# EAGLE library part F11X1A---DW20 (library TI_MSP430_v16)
*** MSP430F11x1A *** DW20

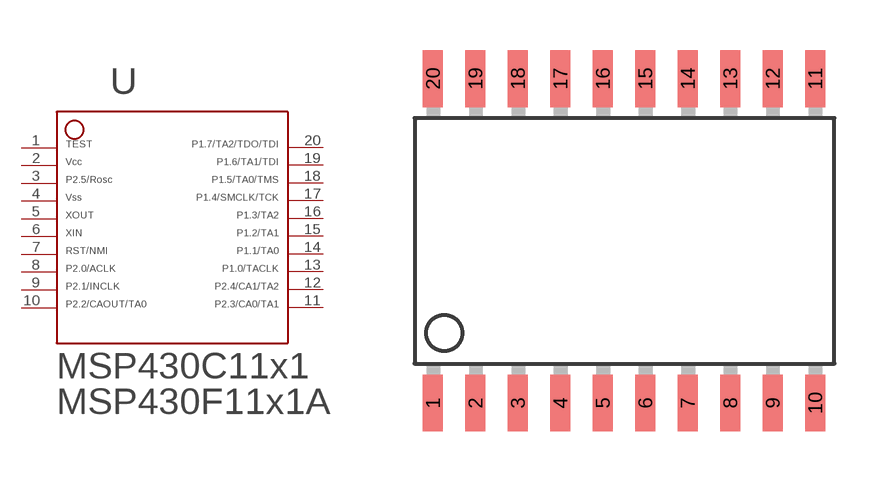
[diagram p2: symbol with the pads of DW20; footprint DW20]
Designator prefix -

## F11X1A---DW20  [DW20]
1  1  in
2  2  pwr
3  3
4  4  pwr
5  5  out
6  6  in
7  7  in
8  8
9  9
10  10
11  11
12  12
13  13
14  14
15  15
16  16
17  17
18  18
19  19
20  20

## Footprint DW20 (pad centres in mm)
*** TI: DW *** JEDEC: R-PDSO-G20 *** 20 PINS ***
smd 0.6 x 1.7: 1 -5.715,-4.85; 2 -4.445,-4.85; 3 -3.175,-4.85; 4 -1.905,-4.85; 5 -0.635,-4.85; 6 0.635,-4.85; 7 1.905,-4.85; 8 3.175,-4.85; 9 4.445,-4.85; 10 5.715,-4.85; 11 5.715,4.85; 12 4.445,4.85; 13 3.175,4.85; 14 1.905,4.85; 15 0.635,4.85; 16 -0.635,4.85; 17 -1.905,4.85; 18 -3.175,4.85; 19 -4.445,4.85; 20 -5.715,4.85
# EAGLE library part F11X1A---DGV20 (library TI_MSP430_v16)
*** MSP430F11x1A *** DGV20

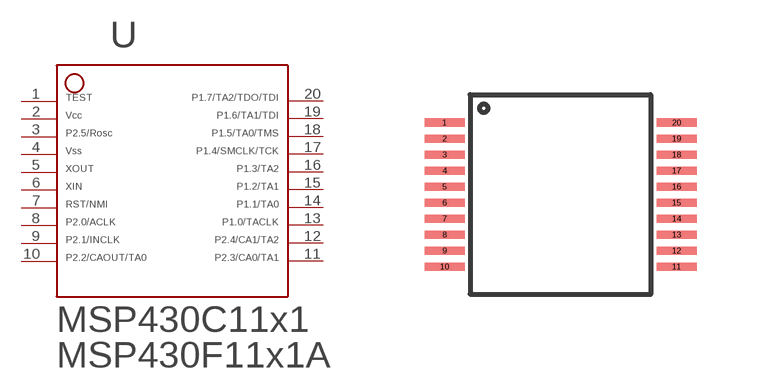
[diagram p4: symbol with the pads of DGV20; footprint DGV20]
Designator prefix -

## F11X1A---DGV20  [DGV20]
1  1  in
2  2  pwr
3  3
4  4  pwr
5  5  out
6  6  in
7  7  in
8  8
9  9
10  10
11  11
12  12
13  13
14  14
15  15
16  16
17  17
18  18
19  19
20  20

## Footprint DGV20 (pad centres in mm)
*** TI: DGV *** JEDEC: R-PDSO-G20 *** 20 PINS ***
smd 1 x 0.2: 1 -2.9,1.8; 2 -2.9,1.4; 3 -2.9,1; 4 -2.9,0.6; 5 -2.9,0.2; 6 -2.9,-0.2; 7 -2.9,-0.6; 8 -2.9,-1; 9 -2.9,-1.4; 10 -2.9,-1.8; 11 2.9,-1.8; 12 2.9,-1.4; 13 2.9,-1; 14 2.9,-0.6; 15 2.9,-0.2; 16 2.9,0.2; 17 2.9,0.6; 18 2.9,1; 19 2.9,1.4; 20 2.9,1.8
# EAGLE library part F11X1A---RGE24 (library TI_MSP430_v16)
*** MSP430F11x1A *** RGE24

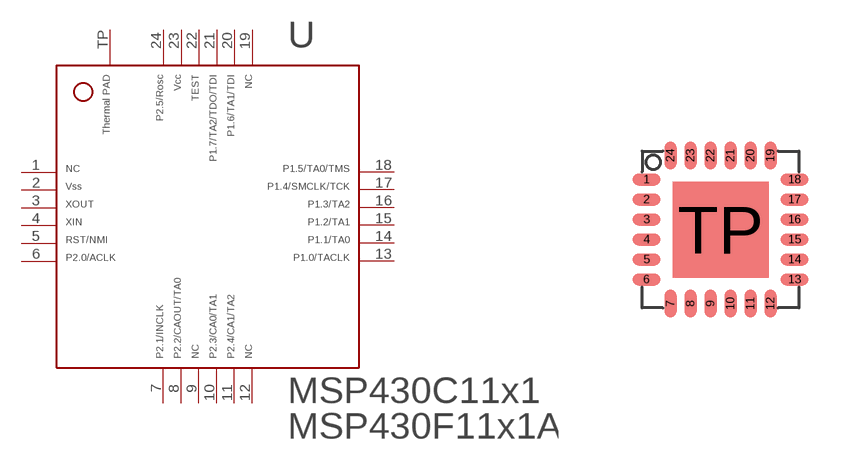
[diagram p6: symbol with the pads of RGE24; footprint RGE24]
Designator prefix -

## F11X1A---RGE24  [RGE24]
1  1  nc
2  2  pwr
3  3  out
4  4  in
5  5  in
6  6
7  7
8  8
9  9  nc
10  10
11  11
12  12  nc
13  13
14  14
15  15
16  16
17  17
18  18
19  19  nc
20  20
21  21
22  22  in
23  23  pwr
24  24
TP  25  pwr

## Footprint RGE24 (pad centres in mm)
*** TI: RGE *** JEDEC: S-PQFP-N24 *** 24 PINS *** ---> PIN25 (exposed thermal die pad) should be connected with GND
smd 0.7 x 0.3: 1 -1.85,1.25; 2 -1.85,0.75; 3 -1.85,0.25; 4 -1.85,-0.25; 5 -1.85,-0.75; 6 -1.85,-1.25; 13 1.85,-1.25; 14 1.85,-0.75; 15 1.85,-0.25; 16 1.85,0.25; 17 1.85,0.75; 18 1.85,1.25
smd 0.3 x 0.7: 7 -1.25,-1.85; 8 -0.75,-1.85; 9 -0.25,-1.85; 10 0.25,-1.85; 11 0.75,-1.85; 12 1.25,-1.85; 19 1.25,1.85; 20 0.75,1.85; 21 0.25,1.85; 22 -0.25,1.85; 23 -0.75,1.85; 24 -1.25,1.85
smd 2.4 x 2.4: TP 0,0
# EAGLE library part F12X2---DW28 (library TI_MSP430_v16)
*** MSP430F12x2 *** DW28

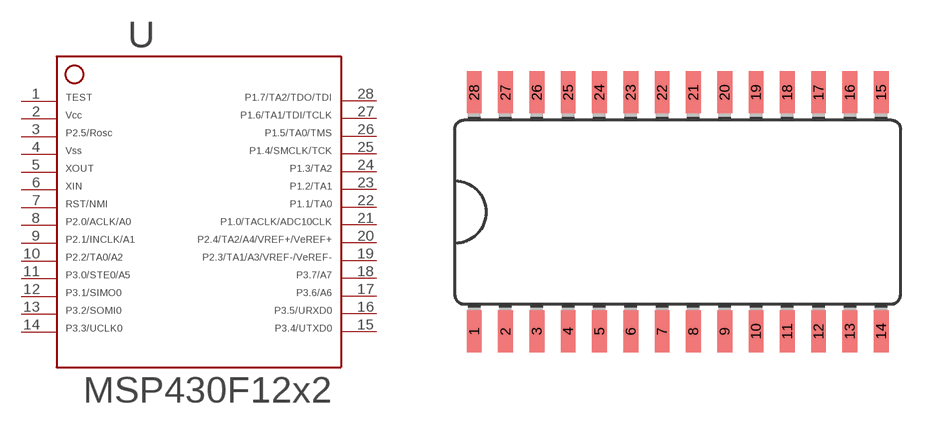
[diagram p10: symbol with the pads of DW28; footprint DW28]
Designator prefix -

## F12X2---DW28  [DW28]
1  1  in
2  2  pwr
3  3
4  4  pwr
5  5  out
6  6  in
7  7  in
8  8
9  9
10  10
11  11
12  12
13  13
14  14
15  15
16  16
17  17
18  18
19  19
20  20
21  21
22  22
23  23
24  24
25  25
26  26
27  27
28  28

## Footprint DW28 (pad centres in mm)
*** TI: DW *** JEDEC: R-PDSO-G28 *** 28 PINS ***
smd 0.6 x 1.7: 1 -8.25,-4.84; 2 -6.98,-4.84; 3 -5.71,-4.84; 4 -4.44,-4.84; 5 -3.17,-4.84; 6 -1.9,-4.84; 7 -0.63,-4.84; 8 0.64,-4.84; 9 1.91,-4.84; 10 3.18,-4.84; 11 4.45,-4.84; 12 5.72,-4.84; 13 6.99,-4.84; 14 8.26,-4.84; 15 8.26,4.86; 16 6.99,4.86; 17 5.72,4.86; 18 4.45,4.86; 19 3.18,4.86; 20 1.91,4.86; 21 0.64,4.86; 22 -0.63,4.86; 23 -1.9,4.86; 24 -3.17,4.86; 25 -4.44,4.86; 26 -5.71,4.86; 27 -6.98,4.86; 28 -8.25,4.86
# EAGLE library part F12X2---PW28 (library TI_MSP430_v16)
*** MSP430F12x2 *** PW28

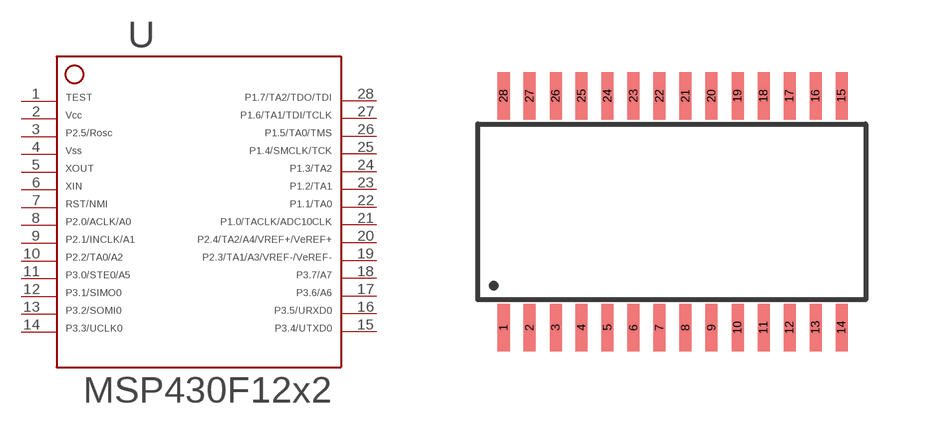
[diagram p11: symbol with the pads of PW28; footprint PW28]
Designator prefix -

## F12X2---PW28  [PW28]
1  1  in
2  2  pwr
3  3
4  4  pwr
5  5  out
6  6  in
7  7  in
8  8
9  9
10  10
11  11
12  12
13  13
14  14
15  15
16  16
17  17
18  18
19  19
20  20
21  21
22  22
23  23
24  24
25  25
26  26
27  27
28  28

## Footprint PW28 (pad centres in mm)
*** TI: DW *** JEDEC: R-PDSO-G28 *** 28 PINS ***
smd 0.3 x 1.2: 1 -4.229,-2.908; 2 -3.579,-2.908; 3 -2.929,-2.908; 4 -2.279,-2.908; 5 -1.629,-2.908; 6 -0.979,-2.908; 7 -0.329,-2.908; 8 0.321,-2.908; 9 0.971,-2.908; 10 1.621,-2.908; 11 2.271,-2.908; 12 2.921,-2.908; 13 3.571,-2.908; 14 4.221,-2.908; 15 4.221,2.892; 16 3.571,2.892; 17 2.921,2.892; 18 2.271,2.892; 19 1.621,2.892; 20 0.971,2.892; 21 0.321,2.892; 22 -0.329,2.892; 23 -0.979,2.892; 24 -1.629,2.892; 25 -2.279,2.892; 26 -2.929,2.892; 27 -3.579,2.892; 28 -4.229,2.892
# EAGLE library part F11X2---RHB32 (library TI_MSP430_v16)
*** MSP430F11x2 *** RHB32

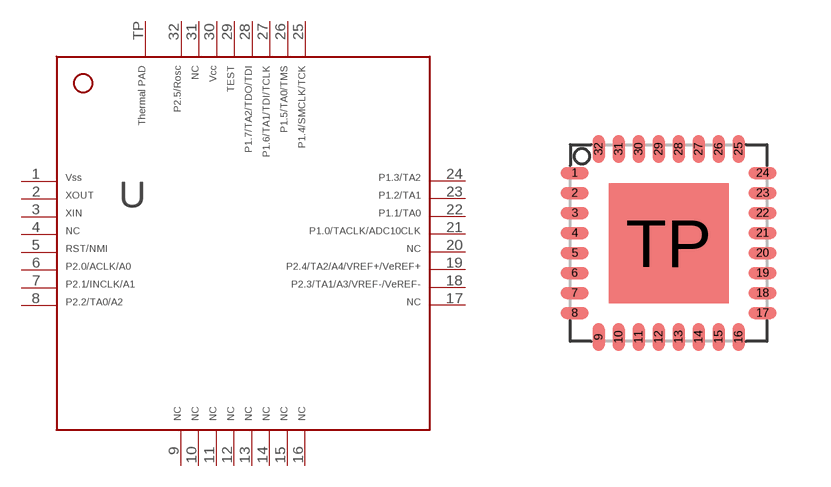
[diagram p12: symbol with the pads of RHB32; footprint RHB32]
Designator prefix -

## F11X2---RHB32  [RHB32]
1  1  pwr
2  2  out
3  3  in
4  4  nc
5  5  in
6  6
7  7
8  8
9  9  nc
10  10  nc
11  11  nc
12  12  nc
13  13  nc
14  14  nc
15  15  nc
16  16  nc
17  17  nc
18  18
19  19
20  20  nc
21  21
22  22
23  23
24  24
25  25
26  26
27  27
28  28
29  29  in
30  30  pwr
31  31  nc
32  32
TP  33  pwr

## Footprint RHB32 (pad centres in mm)
*** TI: RHB *** JEDEC: S-PQFP-N32 *** 32 PINS *** ---> PIN 33 (exposed thermal die pad) should be connected with GND
smd 0.7 x 0.3: 1 -2.35,1.75; 2 -2.35,1.25; 3 -2.35,0.75; 4 -2.35,0.25; 5 -2.35,-0.25; 6 -2.35,-0.75; 7 -2.35,-1.25; 8 -2.35,-1.75; 17 2.35,-1.75; 18 2.35,-1.25; 19 2.35,-0.75; 20 2.35,-0.25; 21 2.35,0.25; 22 2.35,0.75; 23 2.35,1.25; 24 2.35,1.75
smd 0.3 x 0.7: 9 -1.75,-2.35; 10 -1.25,-2.35; 11 -0.75,-2.35; 12 -0.25,-2.35; 13 0.25,-2.35; 14 0.75,-2.35; 15 1.25,-2.35; 16 1.75,-2.35; 25 1.75,2.35; 26 1.25,2.35; 27 0.75,2.35; 28 0.25,2.35; 29 -0.25,2.35; 30 -0.75,2.35; 31 -1.25,2.35; 32 -1.75,2.35
smd 3 x 3: TP 0,0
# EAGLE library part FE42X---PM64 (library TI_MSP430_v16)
*** MSP430FE42x *** PM64

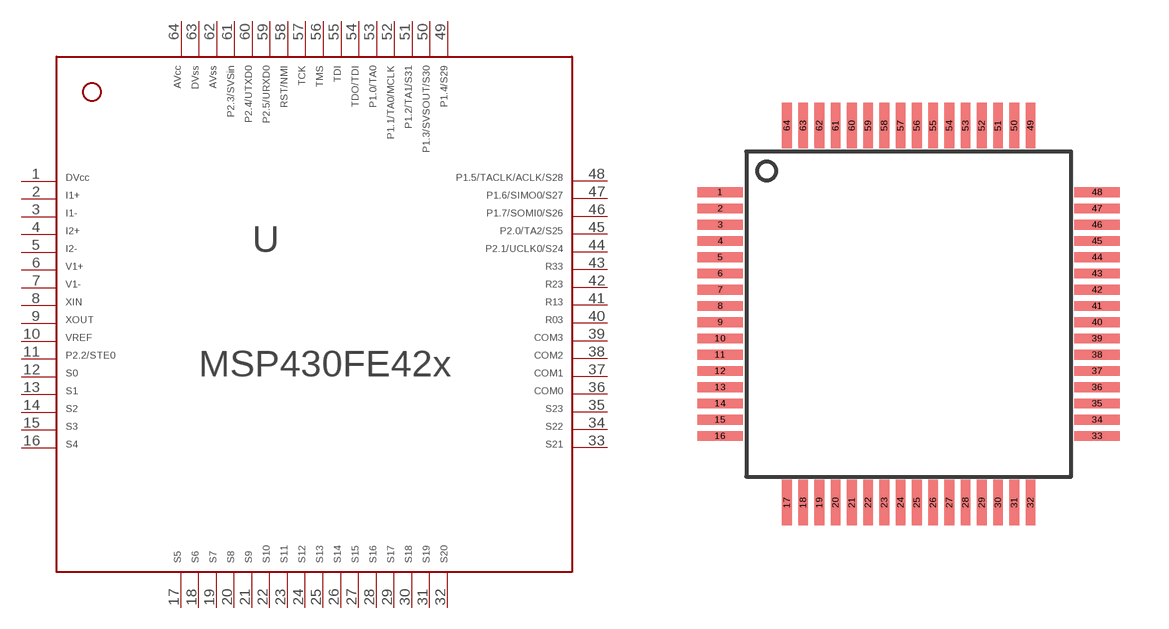
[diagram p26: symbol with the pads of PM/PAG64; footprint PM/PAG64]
Designator prefix -

## FE42X---PM64  [PM/PAG64]
1  1  pwr
2  2  in
3  3  in
4  4  in
5  5  in
6  6  in
7  7  in
8  8  in
9  9  out
10  10
11  11
12  12  out
13  13  out
14  14  out
15  15  out
16  16  out
17  17  out
18  18  out
19  19  out
20  20  out
21  21  out
22  22  out
23  23  out
24  24  out
25  25  out
26  26  out
27  27  out
28  28  out
29  29  out
30  30  out
31  31  out
32  32  out
33  33  out
34  34  out
35  35  out
36  36  out
37  37  out
38  38  out
39  39  out
40  40  in
41  41  in
42  42  in
43  43  out
44  44
45  45
46  46
47  47
48  48
49  49
50  50
51  51
52  52
53  53
54  54
55  55  in
56  56  in
57  57  in
58  58  in
59  59
60  60
61  61
62  62  pwr
63  63  pwr
64  64  pwr

## Footprint PM/PAG64 (pad centres in mm)
*** TI: PM *** JEDEC: S-PQFP-G64 *** 64 PINS ***
smd 1.4 x 0.3: 1 -5.8,3.75; 2 -5.8,3.25; 3 -5.8,2.75; 4 -5.8,2.25; 5 -5.8,1.75; 6 -5.8,1.25; 7 -5.8,0.75; 8 -5.8,0.25; 9 -5.8,-0.25; 10 -5.8,-0.75; 11 -5.8,-1.25; 12 -5.8,-1.75; 13 -5.8,-2.25; 14 -5.8,-2.75; 15 -5.8,-3.25; 16 -5.8,-3.75; 33 5.8,-3.75; 34 5.8,-3.25; 35 5.8,-2.75; 36 5.8,-2.25; 37 5.8,-1.75; 38 5.8,-1.25; 39 5.8,-0.75; 40 5.8,-0.25; 41 5.8,0.25; 42 5.8,0.75; 43 5.8,1.25; 44 5.8,1.75; 45 5.8,2.25; 46 5.8,2.75; 47 5.8,3.25; 48 5.8,3.75
smd 0.3 x 1.4: 17 -3.75,-5.8; 18 -3.25,-5.8; 19 -2.75,-5.8; 20 -2.25,-5.8; 21 -1.75,-5.8; 22 -1.25,-5.8; 23 -0.75,-5.8; 24 -0.25,-5.8; 25 0.25,-5.8; 26 0.75,-5.8; 27 1.25,-5.8; 28 1.75,-5.8; 29 2.25,-5.8; 30 2.75,-5.8; 31 3.25,-5.8; 32 3.75,-5.8; 49 3.75,5.8; 50 3.25,5.8; 51 2.75,5.8; 52 2.25,5.8; 53 1.75,5.8; 54 1.25,5.8; 55 0.75,5.8; 56 0.25,5.8; 57 -0.25,5.8; 58 -0.75,5.8; 59 -1.25,5.8; 60 -1.75,5.8; 61 -2.25,5.8; 62 -2.75,5.8; 63 -3.25,5.8; 64 -3.75,5.8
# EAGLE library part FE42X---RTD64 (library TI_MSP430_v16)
*** MSP430FE42x *** RTD64

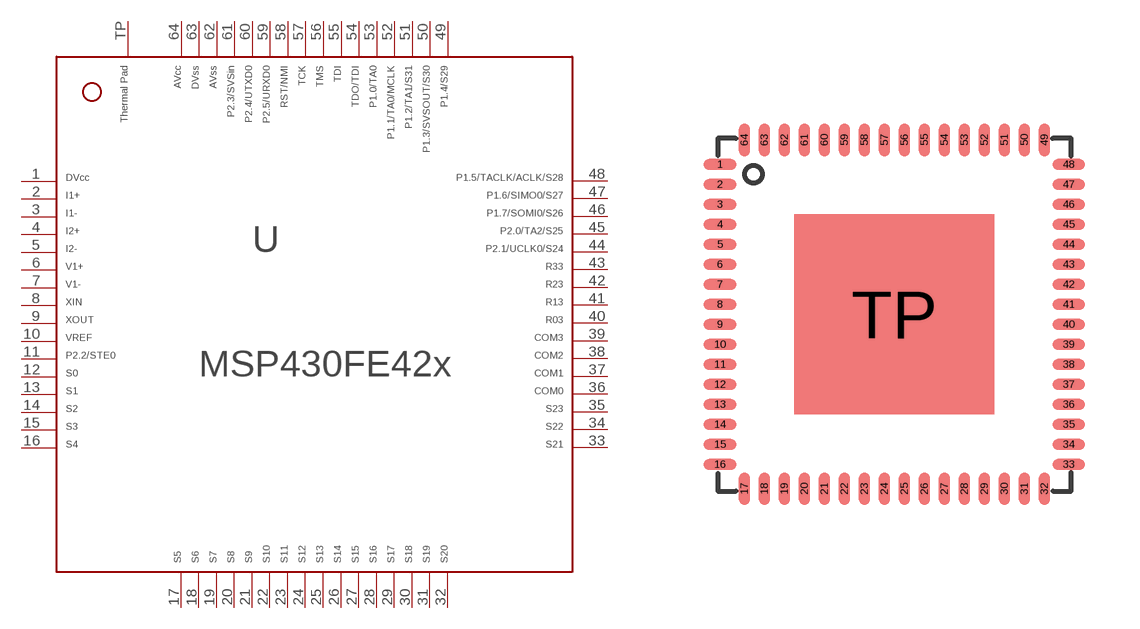
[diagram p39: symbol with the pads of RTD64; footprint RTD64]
Designator prefix -

## FE42X---RTD64  [RTD64]
1  1  pwr
2  2  in
3  3  in
4  4  in
5  5  in
6  6  in
7  7  in
8  8  in
9  9  out
10  10
11  11
12  12  out
13  13  out
14  14  out
15  15  out
16  16  out
17  17  out
18  18  out
19  19  out
20  20  out
21  21  out
22  22  out
23  23  out
24  24  out
25  25  out
26  26  out
27  27  out
28  28  out
29  29  out
30  30  out
31  31  out
32  32  out
33  33  out
34  34  out
35  35  out
36  36  out
37  37  out
38  38  out
39  39  out
40  40  in
41  41  in
42  42  in
43  43  out
44  44
45  45
46  46
47  47
48  48
49  49
50  50
51  51
52  52
53  53
54  54
55  55  in
56  56  in
57  57  in
58  58  in
59  59
60  60
61  61
62  62  pwr
63  63  pwr
64  64  pwr
TP  65  pwr

## Footprint RTD64 (pad centres in mm)
*** TI: RTD *** JEDEC: S-PQFP-N64 *** 64 PINS *** ---> PIN 65 (exposed thermal die pad) should be connected with GND
smd 0.825 x 0.28: 1 -4.36,3.75; 2 -4.36,3.25; 3 -4.36,2.75; 4 -4.36,2.25; 5 -4.36,1.75; 6 -4.36,1.25; 7 -4.36,0.75; 8 -4.36,0.25; 9 -4.36,-0.25; 10 -4.36,-0.75; 11 -4.36,-1.25; 12 -4.36,-1.75; 13 -4.36,-2.25; 14 -4.36,-2.75; 15 -4.36,-3.25; 16 -4.36,-3.75; 33 4.36,-3.75; 34 4.36,-3.25; 35 4.36,-2.75; 36 4.36,-2.25; 37 4.36,-1.75; 38 4.36,-1.25; 39 4.36,-0.75; 40 4.36,-0.25; 41 4.36,0.25; 42 4.36,0.75; 43 4.36,1.25; 44 4.36,1.75; 45 4.36,2.25; 46 4.36,2.75; 47 4.36,3.25; 48 4.36,3.75
smd 0.28 x 0.825: 17 -3.75,-4.36; 18 -3.25,-4.36; 19 -2.75,-4.36; 20 -2.25,-4.36; 21 -1.75,-4.36; 22 -1.25,-4.36; 23 -0.75,-4.36; 24 -0.25,-4.36; 25 0.25,-4.36; 26 0.75,-4.36; 27 1.25,-4.36; 28 1.75,-4.36; 29 2.25,-4.36; 30 2.75,-4.36; 31 3.25,-4.36; 32 3.75,-4.36; 49 3.75,4.36; 50 3.25,4.36; 51 2.75,4.36; 52 2.25,4.36; 53 1.75,4.36; 54 1.25,4.36; 55 0.75,4.36; 56 0.25,4.36; 57 -0.25,4.36; 58 -0.75,4.36; 59 -1.25,4.36; 60 -1.75,4.36; 61 -2.25,4.36; 62 -2.75,4.36; 63 -3.25,4.36; 64 -3.75,4.36
smd 5 x 5: TP 0,0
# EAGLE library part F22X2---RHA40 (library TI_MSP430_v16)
***MSP430F22x2***RHA40

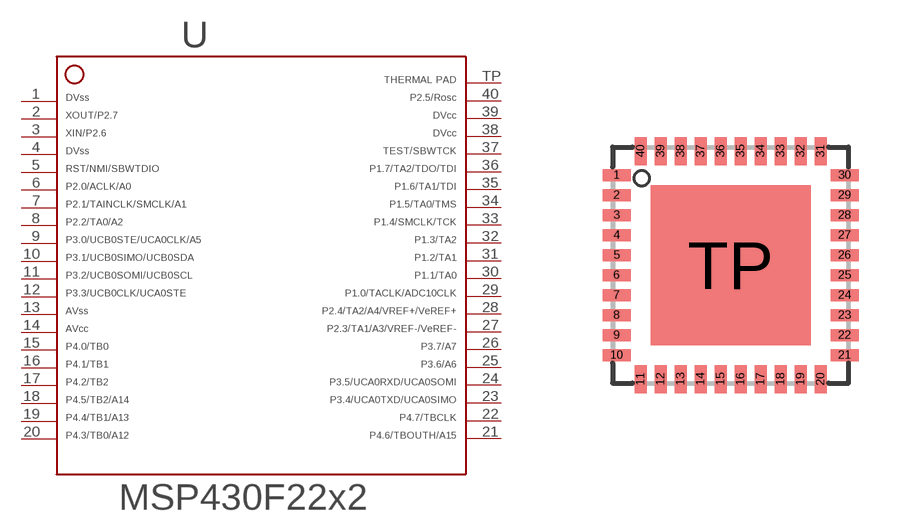
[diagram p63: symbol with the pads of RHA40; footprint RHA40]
Designator prefix -

## F22X2---RHA40  [RHA40]
1  1  pwr
2  2
3  3
4  4  pwr
5  5
6  6
7  7
8  8
9  9
10  10
11  11
12  12
13  13  pwr
14  14  pwr
15  15
16  16
17  17
18  18
19  19
20  20
21  21
22  22
23  23
24  24
25  25
26  26
27  27
28  28
29  29
30  30
31  31
32  32
33  33
34  34
35  35
36  36
37  37  in
38  38  pwr
39  39  pwr
40  40
TP  TP  pwr

## Footprint RHA40 (pad centres in mm)
*** TI: RHA *** JEDEC: S-PQFP-N40 *** 40 PINS *** ---> PIN TP (exposed thermal die pad) should be connected with GND
smd 0.7 x 0.3: 1 -2.85,2.25; 2 -2.85,1.75; 3 -2.85,1.25; 4 -2.85,0.75; 5 -2.85,0.25; 6 -2.85,-0.25; 7 -2.85,-0.75; 8 -2.85,-1.25; 9 -2.85,-1.75; 10 -2.85,-2.25; 21 2.85,-2.25; 22 2.85,-1.75; 23 2.85,-1.25; 24 2.85,-0.75; 25 2.85,-0.25; 26 2.85,0.25; 27 2.85,0.75; 28 2.85,1.25; 29 2.85,1.75; 30 2.85,2.25
smd 0.3 x 0.7: 11 -2.25,-2.85; 12 -1.75,-2.85; 13 -1.25,-2.85; 14 -0.75,-2.85; 15 -0.25,-2.85; 16 0.25,-2.85; 17 0.75,-2.85; 18 1.25,-2.85; 19 1.75,-2.85; 20 2.25,-2.85; 31 2.25,2.85; 32 1.75,2.85; 33 1.25,2.85; 34 0.75,2.85; 35 0.25,2.85; 36 -0.25,2.85; 37 -0.75,2.85; 38 -1.25,2.85; 39 -1.75,2.85; 40 -2.25,2.85
smd 4 x 4: TP 0,0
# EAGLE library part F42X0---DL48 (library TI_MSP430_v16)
***MSP430F42x0***DL48

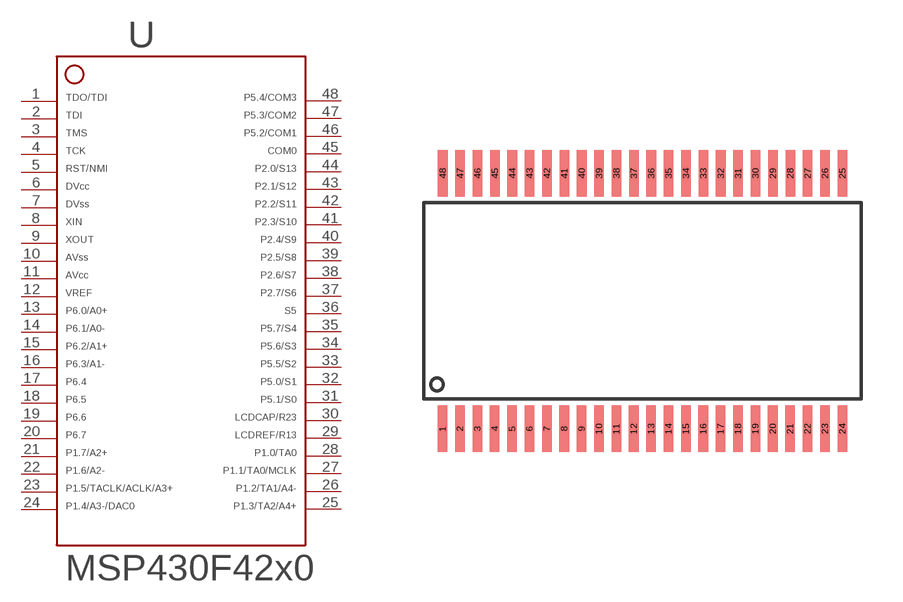
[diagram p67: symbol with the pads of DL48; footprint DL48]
Designator prefix -

## F42X0---DL48  [DL48]
1  1
2  2  in
3  3  in
4  4  in
5  5  in
6  6  pwr
7  7  pwr
8  8  in
9  9  out
10  10  pwr
11  11  pwr
12  12
13  13
14  14
15  15
16  16
17  17
18  18
19  19
20  20
21  21
22  22
23  23
24  24
25  25
26  26
27  27
28  28
29  29
30  30
31  31
32  32
33  33
34  34
35  35
36  36  out
37  37  in
38  38  in
39  39
40  40
41  41
42  42
43  43
44  44
45  45  in
46  46
47  47
48  48

## Footprint DL48 (pad centres in mm)
*** TI: DL *** JEDEC: R-PDSO-G48 *** 48 PINS ***
smd 0.35 x 1.705: 1 -7.305,-4.67; 2 -6.67,-4.67; 3 -6.035,-4.67; 4 -5.4,-4.67; 5 -4.765,-4.67; 6 -4.13,-4.67; 7 -3.495,-4.67; 8 -2.86,-4.67; 9 -2.225,-4.67; 10 -1.59,-4.67; 11 -0.955,-4.67; 12 -0.32,-4.67; 13 0.315,-4.67; 14 0.95,-4.67; 15 1.585,-4.67; 16 2.22,-4.67; 17 2.855,-4.67; 18 3.49,-4.67; 19 4.125,-4.67; 20 4.76,-4.67; 21 5.395,-4.67; 22 6.03,-4.67; 23 6.665,-4.67; 24 7.3,-4.67; 25 7.305,4.67; 26 6.67,4.67; 27 6.035,4.67; 28 5.4,4.67; 29 4.765,4.67; 30 4.13,4.67; 31 3.495,4.67; 32 2.86,4.67; 33 2.225,4.67; 34 1.59,4.67; 35 0.955,4.67; 36 0.32,4.67; 37 -0.315,4.67; 38 -0.95,4.67; 39 -1.585,4.67; 40 -2.22,4.67; 41 -2.855,4.67; 42 -3.49,4.67; 43 -4.125,4.67; 44 -4.76,4.67; 45 -5.395,4.67; 46 -6.03,4.67; 47 -6.665,4.67; 48 -7.3,4.67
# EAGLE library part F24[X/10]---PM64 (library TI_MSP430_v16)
***MSP430F24[x/10]***PM64

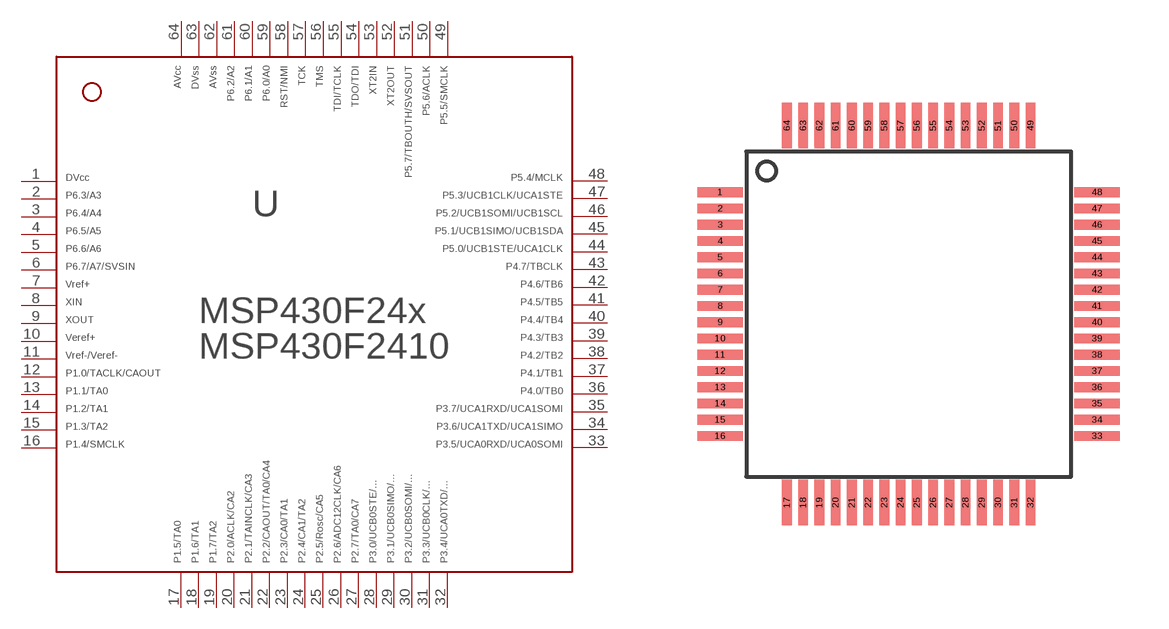
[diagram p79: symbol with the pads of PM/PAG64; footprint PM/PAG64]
Designator prefix -

## F24[X/10]---PM64  [PM/PAG64]
1  1  pwr
2  2
3  3
4  4
5  5
6  6
7  7  out
8  8  in
9  9  out
10  10  out
11  11  in
12  12
13  13
14  14
15  15
16  16
17  17
18  18
19  19
20  20
21  21
22  22
23  23
24  24
25  25
26  26
27  27
28  28
29  29
30  30
31  31
32  32
33  33
34  34
35  35
36  36
37  37
38  38
39  39
40  40
41  41
42  42
43  43
44  44
45  45
46  46
47  47
48  48
49  49
50  50
51  51
52  52  out
53  53  in
54  54
55  55  in
56  56  in
57  57  in
58  58  in
59  59
60  60
61  61
62  62  pwr
63  63  pwr
64  64  pwr

## Footprint PM/PAG64 (pad centres in mm)
*** TI: PM *** JEDEC: S-PQFP-G64 *** 64 PINS ***
smd 1.4 x 0.3: 1 -5.8,3.75; 2 -5.8,3.25; 3 -5.8,2.75; 4 -5.8,2.25; 5 -5.8,1.75; 6 -5.8,1.25; 7 -5.8,0.75; 8 -5.8,0.25; 9 -5.8,-0.25; 10 -5.8,-0.75; 11 -5.8,-1.25; 12 -5.8,-1.75; 13 -5.8,-2.25; 14 -5.8,-2.75; 15 -5.8,-3.25; 16 -5.8,-3.75; 33 5.8,-3.75; 34 5.8,-3.25; 35 5.8,-2.75; 36 5.8,-2.25; 37 5.8,-1.75; 38 5.8,-1.25; 39 5.8,-0.75; 40 5.8,-0.25; 41 5.8,0.25; 42 5.8,0.75; 43 5.8,1.25; 44 5.8,1.75; 45 5.8,2.25; 46 5.8,2.75; 47 5.8,3.25; 48 5.8,3.75
smd 0.3 x 1.4: 17 -3.75,-5.8; 18 -3.25,-5.8; 19 -2.75,-5.8; 20 -2.25,-5.8; 21 -1.75,-5.8; 22 -1.25,-5.8; 23 -0.75,-5.8; 24 -0.25,-5.8; 25 0.25,-5.8; 26 0.75,-5.8; 27 1.25,-5.8; 28 1.75,-5.8; 29 2.25,-5.8; 30 2.75,-5.8; 31 3.25,-5.8; 32 3.75,-5.8; 49 3.75,5.8; 50 3.25,5.8; 51 2.75,5.8; 52 2.25,5.8; 53 1.75,5.8; 54 1.25,5.8; 55 0.75,5.8; 56 0.25,5.8; 57 -0.25,5.8; 58 -0.75,5.8; 59 -1.25,5.8; 60 -1.75,5.8; 61 -2.25,5.8; 62 -2.75,5.8; 63 -3.25,5.8; 64 -3.75,5.8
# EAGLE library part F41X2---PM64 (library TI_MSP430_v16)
***MSP430F41x2***PM64

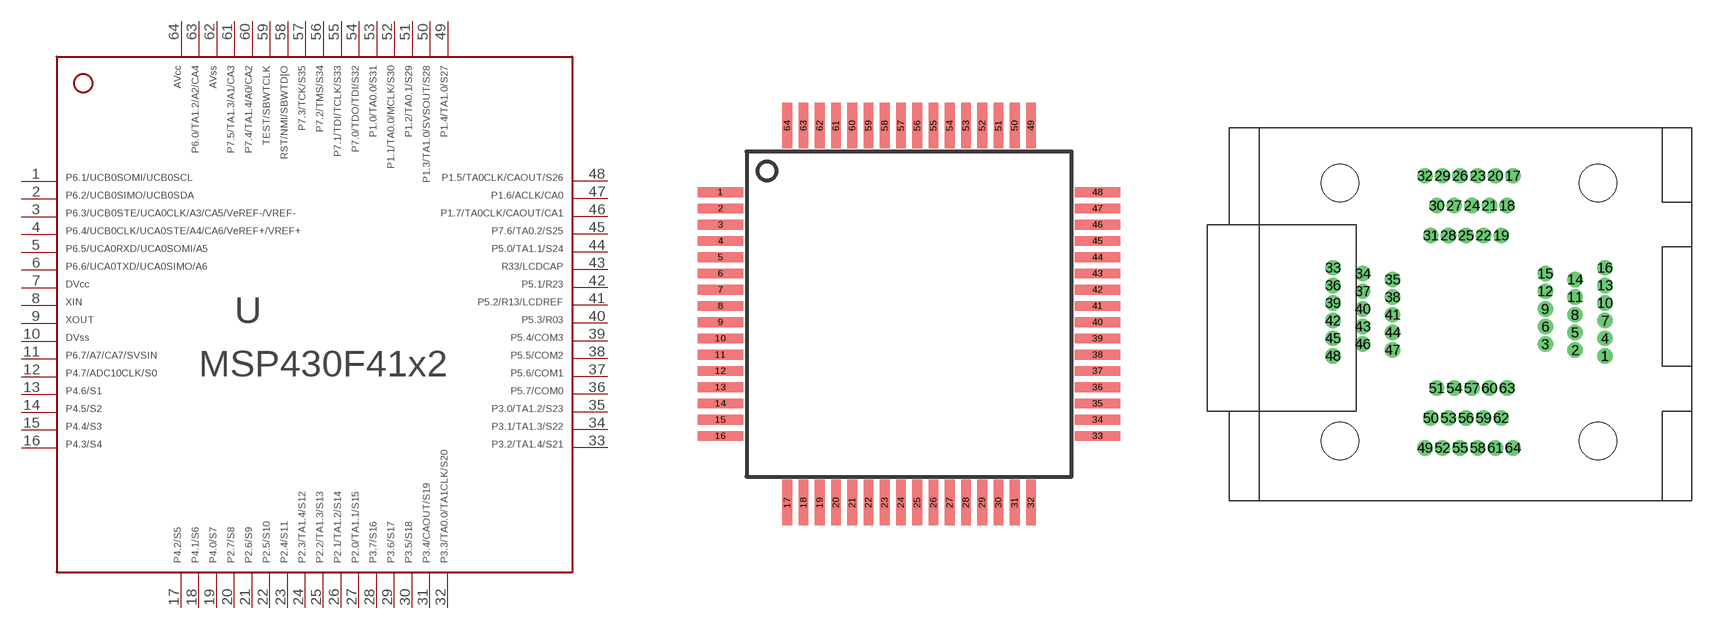
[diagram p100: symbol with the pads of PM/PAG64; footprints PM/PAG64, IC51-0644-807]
Designator prefix -

## F41X2---PM64  [PM/PAG64]
1  1
2  2
3  3
4  4
5  5
6  6
7  7  pwr
8  8  in
9  9  out
10  10  pwr
11  11
12  12
13  13
14  14
15  15
16  16
17  17
18  18
19  19
20  20
21  21
22  22
23  23
24  24
25  25
26  26
27  27
28  28
29  29
30  30
31  31
32  32
33  33
34  34
35  35
36  36
37  37
38  38
39  39
40  40
41  41
42  42
43  43
44  44
45  45
46  46
47  47
48  48
49  49
50  50
51  51
52  52
53  53
54  54
55  55  in
56  56  in
57  57  in
58  58  in
59  59
60  60
61  61
62  62  pwr
63  63  pwr
64  64  pwr

## F41X2---PM64QFP64-SOCKET  [IC51-0644-807]
Pads as for PM/PAG64

## Footprint PM/PAG64 (pad centres in mm)
*** TI: PM *** JEDEC: S-PQFP-G64 *** 64 PINS ***
smd 1.4 x 0.3: 1 -5.8,3.75; 2 -5.8,3.25; 3 -5.8,2.75; 4 -5.8,2.25; 5 -5.8,1.75; 6 -5.8,1.25; 7 -5.8,0.75; 8 -5.8,0.25; 9 -5.8,-0.25; 10 -5.8,-0.75; 11 -5.8,-1.25; 12 -5.8,-1.75; 13 -5.8,-2.25; 14 -5.8,-2.75; 15 -5.8,-3.25; 16 -5.8,-3.75; 33 5.8,-3.75; 34 5.8,-3.25; 35 5.8,-2.75; 36 5.8,-2.25; 37 5.8,-1.75; 38 5.8,-1.25; 39 5.8,-0.75; 40 5.8,-0.25; 41 5.8,0.25; 42 5.8,0.75; 43 5.8,1.25; 44 5.8,1.75; 45 5.8,2.25; 46 5.8,2.75; 47 5.8,3.25; 48 5.8,3.75
smd 0.3 x 1.4: 17 -3.75,-5.8; 18 -3.25,-5.8; 19 -2.75,-5.8; 20 -2.25,-5.8; 21 -1.75,-5.8; 22 -1.25,-5.8; 23 -0.75,-5.8; 24 -0.25,-5.8; 25 0.25,-5.8; 26 0.75,-5.8; 27 1.25,-5.8; 28 1.75,-5.8; 29 2.25,-5.8; 30 2.75,-5.8; 31 3.25,-5.8; 32 3.75,-5.8; 49 3.75,5.8; 50 3.25,5.8; 51 2.75,5.8; 52 2.25,5.8; 53 1.75,5.8; 54 1.25,5.8; 55 0.75,5.8; 56 0.25,5.8; 57 -0.25,5.8; 58 -0.75,5.8; 59 -1.25,5.8; 60 -1.75,5.8; 61 -2.25,5.8; 62 -2.75,5.8; 63 -3.25,5.8; 64 -3.75,5.8

## Footprint IC51-0644-807 (pad centres in mm)
Yamaichi socket for PM Packages *** TI: PM *** JEDEC: S-PQFP-G64 *** 64 PINS ***
drill 0.8 pad 1.27 round: 1 11.652,-4.194; 2 9.112,-3.694; 3 6.572,-3.194; 4 11.652,-2.694; 5 9.112,-2.194; 6 6.572,-1.694; 7 11.652,-1.194; 8 9.112,-0.694; 9 6.572,-0.194; 10 11.652,0.306; 11 9.112,0.806; 12 6.572,1.306; 13 11.652,1.806; 14 9.112,2.306; 15 6.572,2.806; 16 11.652,3.306; 17 3.822,11.136; 18 3.322,8.596; 19 2.822,6.056; 20 2.322,11.136; 21 1.822,8.596; 22 1.322,6.056; 23 0.822,11.136; 24 0.322,8.596; 25 -0.178,6.056; 26 -0.678,11.136; 27 -1.178,8.596; 28 -1.678,6.056; 29 -2.178,11.136; 30 -2.678,8.596; 31 -3.178,6.056; 32 -3.678,11.136; 33 -11.508,3.306; 34 -8.968,2.806; 35 -6.428,2.306; 36 -11.508,1.806; 37 -8.968,1.306; 38 -6.428,0.806; 39 -11.508,0.306; 40 -8.968,-0.194; 41 -6.428,-0.694; 42 -11.508,-1.194; 43 -8.968,-1.694; 44 -6.428,-2.194; 45 -11.508,-2.694; 46 -8.968,-3.194; 47 -6.428,-3.694; 48 -11.508,-4.194; 49 -3.678,-12.024; 50 -3.178,-9.484; 51 -2.678,-6.944; 52 -2.178,-12.024; 53 -1.678,-9.484; 54 -1.178,-6.944; 55 -0.678,-12.024; 56 -0.178,-9.484; 57 0.322,-6.944; 58 0.822,-12.024; 59 1.322,-9.484; 60 1.822,-6.944; 61 2.322,-12.024; 62 2.822,-9.484; 63 3.322,-6.944; 64 3.822,-12.024
hole 3.2 at -10.922,10.541
hole 3.2 at 11.049,10.541
hole 3.2 at 11.049,-11.43
hole 3.2 at -10.922,-11.43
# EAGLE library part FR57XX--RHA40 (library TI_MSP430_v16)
*** MSP430FR57xx *** 40-PIN RHA (QFN) ***

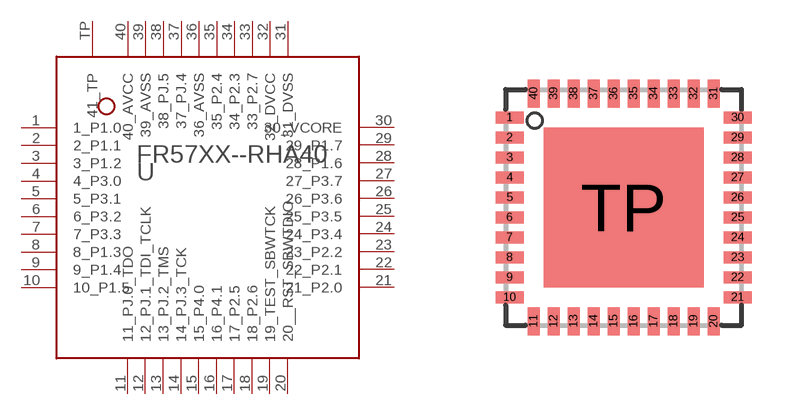
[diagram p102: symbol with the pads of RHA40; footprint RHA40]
Designator prefix -

## FR57XX--RHA40RHAPACKAGE  [RHA40]
1  1_P1.0  pas
2  2_P1.1  pas
3  3_P1.2  pas
4  4_P3.0  pas
5  5_P3.1  pas
6  6_P3.2  pas
7  7_P3.3  pas
8  8_P1.3  pas
9  9_P1.4  pas
10  10_P1.5  pas
11  11_PJ.0_TDO  pas
12  12_PJ.1_TDI_TCLK  pas
13  13_PJ.2_TMS  pas
14  14_PJ.3_TCK  pas
15  15_P4.0  pas
16  16_P4.1  pas
17  17_P2.5  pas
18  18_P2.6  pas
19  19_TEST_SBWTCK  pas
20  20__RST_SBWTDIO  pas
21  21_P2.0  pas
22  22_P2.1  pas
23  23_P2.2  pas
24  24_P3.4  pas
25  25_P3.5  pas
26  26_P3.6  pas
27  27_P3.7  pas
28  28_P1.6  pas
29  29_P1.7  pas
30  30_VCORE  pas
31  31_DVSS  pas
32  32_DVCC  pas
33  33_P2.7  pas
34  34_P2.3  pas
35  35_P2.4  pas
36  36_AVSS  pas
37  37_PJ.4  pas
38  38_PJ.5  pas
39  39_AVSS  pas
40  40_AVCC  pas
TP  41_TP  pas

## Footprint RHA40 (pad centres in mm)
*** TI: RHA *** JEDEC: S-PQFP-N40 *** 40 PINS *** ---> PIN TP (exposed thermal die pad) should be connected with GND
smd 0.7 x 0.3: 1 -2.85,2.25; 2 -2.85,1.75; 3 -2.85,1.25; 4 -2.85,0.75; 5 -2.85,0.25; 6 -2.85,-0.25; 7 -2.85,-0.75; 8 -2.85,-1.25; 9 -2.85,-1.75; 10 -2.85,-2.25; 21 2.85,-2.25; 22 2.85,-1.75; 23 2.85,-1.25; 24 2.85,-0.75; 25 2.85,-0.25; 26 2.85,0.25; 27 2.85,0.75; 28 2.85,1.25; 29 2.85,1.75; 30 2.85,2.25
smd 0.3 x 0.7: 11 -2.25,-2.85; 12 -1.75,-2.85; 13 -1.25,-2.85; 14 -0.75,-2.85; 15 -0.25,-2.85; 16 0.25,-2.85; 17 0.75,-2.85; 18 1.25,-2.85; 19 1.75,-2.85; 20 2.25,-2.85; 31 2.25,2.85; 32 1.75,2.85; 33 1.25,2.85; 34 0.75,2.85; 35 0.25,2.85; 36 -0.25,2.85; 37 -0.75,2.85; 38 -1.25,2.85; 39 -1.75,2.85; 40 -2.25,2.85
smd 4 x 4: TP 0,0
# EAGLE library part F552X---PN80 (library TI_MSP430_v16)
***MSP430F552X***PN80 http://www.ti.com/lit/gpn/msp430f5529 Rev1.0 06/2010 For F552X where X is 1,5,7,9

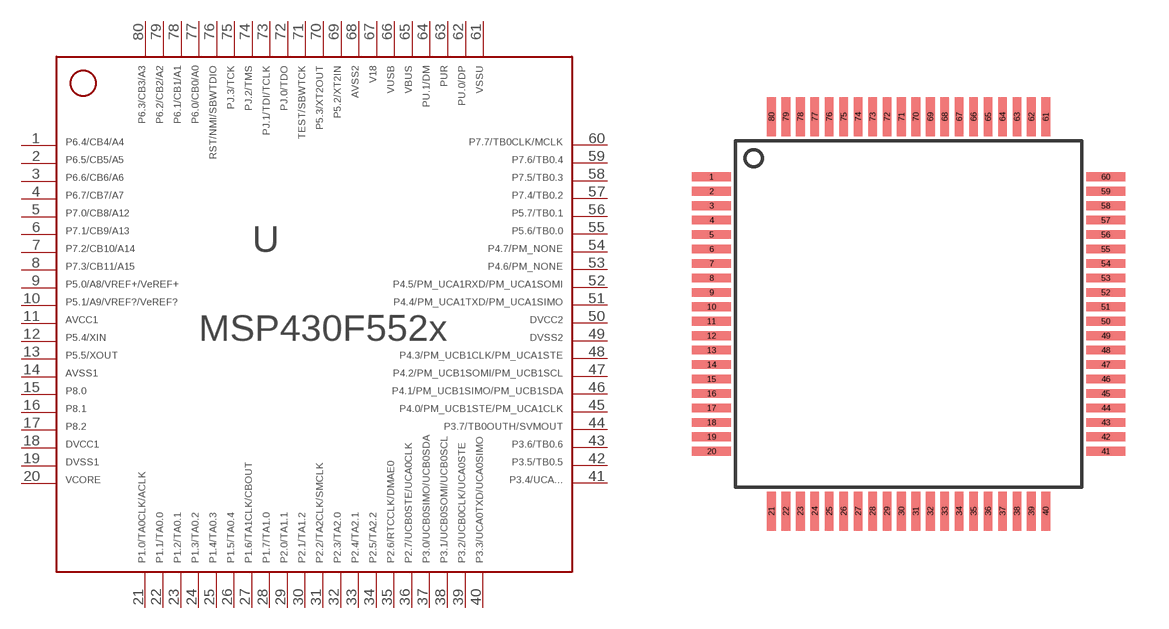
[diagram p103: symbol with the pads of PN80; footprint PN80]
Designator prefix -

## F552X---PN80  [PN80]
1  1
2  2
3  3
4  4
5  5
6  6
7  7
8  8
9  9
10  10
11  11  pwr
12  12
13  13
14  14  pwr
15  15
16  16
17  17
18  18  pwr
19  19  pwr
20  20  pwr
21  21
22  22
23  23
24  24
25  25
26  26
27  27
28  28
29  29
30  30
31  31
32  32
33  33
34  34
35  35
36  36
37  37
38  38
39  39
40  40
41  41
42  42
43  43
44  44
45  45
46  46
47  47
48  48
49  49  pwr
50  50  pwr
51  51
52  52
53  53
54  54
55  55
56  56
57  57
58  58
59  59
60  60
61  61  pwr
62  62
63  63
64  64
65  65  pwr
66  66  pwr
67  67  pwr
68  68  pwr
69  69
70  70
71  71  in
72  72
73  73
74  74
75  75
76  76
77  77
78  78
79  79
80  80

## Footprint PN80 (pad centres in mm)
*** TI: PN *** JEDEC: S-PQFP-G80 *** 80 PINS ***
smd 1.35 x 0.3: 1 -6.825,4.75; 2 -6.825,4.25; 3 -6.825,3.75; 4 -6.825,3.25; 5 -6.825,2.75; 6 -6.825,2.25; 7 -6.825,1.75; 8 -6.825,1.25; 9 -6.825,0.75; 10 -6.825,0.25; 11 -6.825,-0.25; 12 -6.825,-0.75; 13 -6.825,-1.25; 14 -6.825,-1.75; 15 -6.825,-2.25; 16 -6.825,-2.75; 17 -6.825,-3.25; 18 -6.825,-3.75; 19 -6.825,-4.25; 20 -6.825,-4.75; 41 6.825,-4.75; 42 6.825,-4.25; 43 6.825,-3.75; 44 6.825,-3.25; 45 6.825,-2.75; 46 6.825,-2.25; 47 6.825,-1.75; 48 6.825,-1.25; 49 6.825,-0.75; 50 6.825,-0.25; 51 6.825,0.25; 52 6.825,0.75; 53 6.825,1.25; 54 6.825,1.75; 55 6.825,2.25; 56 6.825,2.75; 57 6.825,3.25; 58 6.825,3.75; 59 6.825,4.25; 60 6.825,4.75
smd 0.3 x 1.35: 21 -4.75,-6.825; 22 -4.25,-6.825; 23 -3.75,-6.825; 24 -3.25,-6.825; 25 -2.75,-6.825; 26 -2.25,-6.825; 27 -1.75,-6.825; 28 -1.25,-6.825; 29 -0.75,-6.825; 30 -0.25,-6.825; 31 0.25,-6.825; 32 0.75,-6.825; 33 1.25,-6.825; 34 1.75,-6.825; 35 2.25,-6.825; 36 2.75,-6.825; 37 3.25,-6.825; 38 3.75,-6.825; 39 4.25,-6.825; 40 4.75,-6.825; 61 4.75,6.825; 62 4.25,6.825; 63 3.75,6.825; 64 3.25,6.825; 65 2.75,6.825; 66 2.25,6.825; 67 1.75,6.825; 68 1.25,6.825; 69 0.75,6.825; 70 0.25,6.825; 71 -0.25,6.825; 72 -0.75,6.825; 73 -1.25,6.825; 74 -1.75,6.825; 75 -2.25,6.825; 76 -2.75,6.825; 77 -3.25,6.825; 78 -3.75,6.825; 79 -4.25,6.825; 80 -4.75,6.825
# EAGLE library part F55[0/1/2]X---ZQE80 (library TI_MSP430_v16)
***MSP430F55[1X/2X] *** ZQE80 Rev.1.0 06\2010 http://focus.ti.com/docs/prod/folders/print/msp430f5529.html Datasheet: http://www.ti.com/lit/gpn/msp430f5529 MSP430F5528IZQE, MSP430F5526IZQE, MSP430F5524IZQE, MSP430F5522IZQE, MSP430F5514IZQE, MSP430F5513IZQE

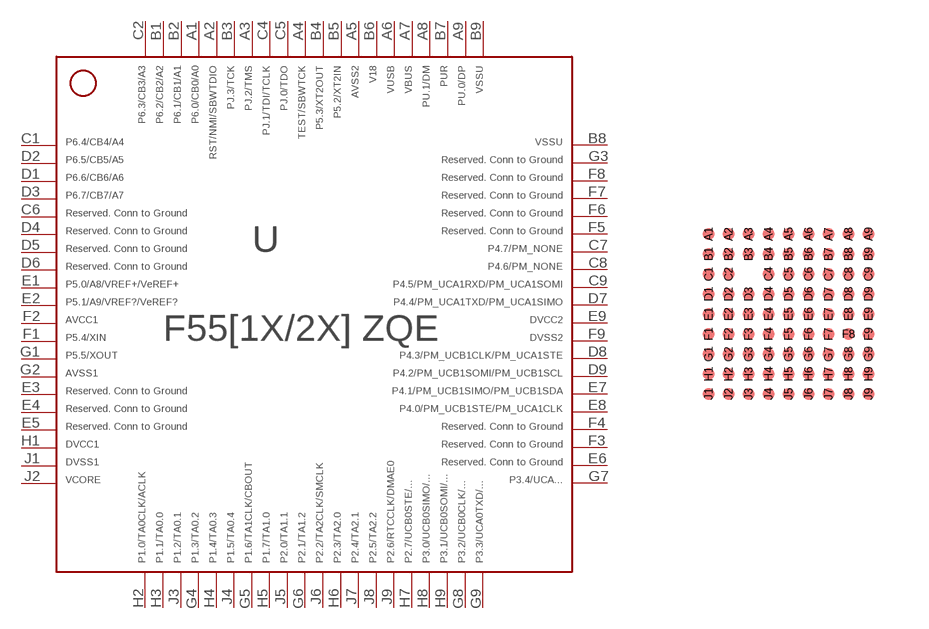
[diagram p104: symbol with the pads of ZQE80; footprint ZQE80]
Designator prefix -

## F55[0/1/2]X---ZQE80  [ZQE80]
A1  A1
A2  A2
A3  A3
A4  A4  in
A5  A5  pwr
A6  A6  pwr
A7  A7  pwr
A8  A8
A9  A9
B1  B1
B2  B2
B3  B3
B4  B4
B5  B5
B6  B6  pwr
B7  B7
B8  B8  pwr
B9  B9  pwr
C1  C1
C2  C2
C4  C4
C5  C5
C6  C6
C7  C7
C8  C8
C9  C9
D1  D1
D2  D2
D3  D3
D4  D4
D5  D5
D6  D6
D7  D7
D8  D8
D9  D9
E1  E1
E2  E2
E3  E3
E4  E4
E5  E5
E6  E6
E7  E7
E8  E8
E9  E9  pwr
F1  F1
F2  F2  pwr
F3  F3
F4  F4
F5  F5
F6  F6
F7  F7
F8  F8
F9  F9  pwr
G1  G1
G2  G2  pwr
G3  G3
G4  G4
G5  G5
G6  G6
G7  G7
G8  G8
G9  G9
H1  H1  pwr
H2  H2
H3  H3
H4  H4
H5  H5
H6  H6
H7  H7
H8  H8
H9  H9
J1  J1  pwr
J2  J2  pwr
J3  J3
J4  J4
J5  J5
J6  J6
J7  J7
J8  J8
J9  J9

## Footprint ZQE80 (pad centres in mm)
*** TI: ZQE *** JEDEC: S-PBGA-N80 -- BGA MICROSTAR JUNIOR *** 80 PINS *** ** 0.5 mm pitch
smd 0.3 x 0.3: A1 -2,2; A2 -1.5,2; A3 -1,2; A4 -0.5,2; A5 0,2; A6 0.5,2; A7 1,2; A8 1.5,2; A9 2,2; B1 -2,1.5; B2 -1.5,1.5; B3 -1,1.5; B4 -0.5,1.5; B5 0,1.5; B6 0.5,1.5; B7 1,1.5; B8 1.5,1.5; B9 2,1.5; C1 -2,1; C2 -1.5,1; C4 -0.5,1; C5 0,1; C6 0.5,1; C7 1,1; C8 1.5,1; C9 2,1; D1 -2,0.5; D2 -1.5,0.5; D3 -1,0.5; D4 -0.5,0.5; D5 0,0.5; D6 0.5,0.5; D7 1,0.5; D8 1.5,0.5; D9 2,0.5; E1 -2,0; E2 -1.5,0; E3 -1,0; E4 -0.5,0; E5 0,0; E6 0.5,0; E7 1,0; E8 1.5,0; E9 2,0; F1 -2,-0.5; F2 -1.5,-0.5; F3 -1,-0.5; F4 -0.5,-0.5; F5 0,-0.5; F6 0.5,-0.5; F7 1,-0.5; F8 1.5,-0.5; F9 2,-0.5; G1 -2,-1; G2 -1.5,-1; G3 -1,-1; G4 -0.5,-1; G5 0,-1; G6 0.5,-1; G7 1,-1; G8 1.5,-1; G9 2,-1; H1 -2,-1.5; H2 -1.5,-1.5; H3 -1,-1.5; H4 -0.5,-1.5; H5 0,-1.5; H6 0.5,-1.5; H7 1,-1.5; H8 1.5,-1.5; H9 2,-1.5; J1 -2,-2; J2 -1.5,-2; J3 -1,-2; J4 -0.5,-2; J5 0,-2; J6 0.5,-2; J7 1,-2; J8 1.5,-2; J9 2,-2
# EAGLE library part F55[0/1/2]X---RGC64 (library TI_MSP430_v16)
***F55[0/1/2]X***RGC64 Rev. 1.0 06/2010 "http://www.ti.com/lit/gpn/msp430f5529" "http://www.ti.com/lit/gpn/msp430f5509" F5513/F5514 with limited Functions on some Pins

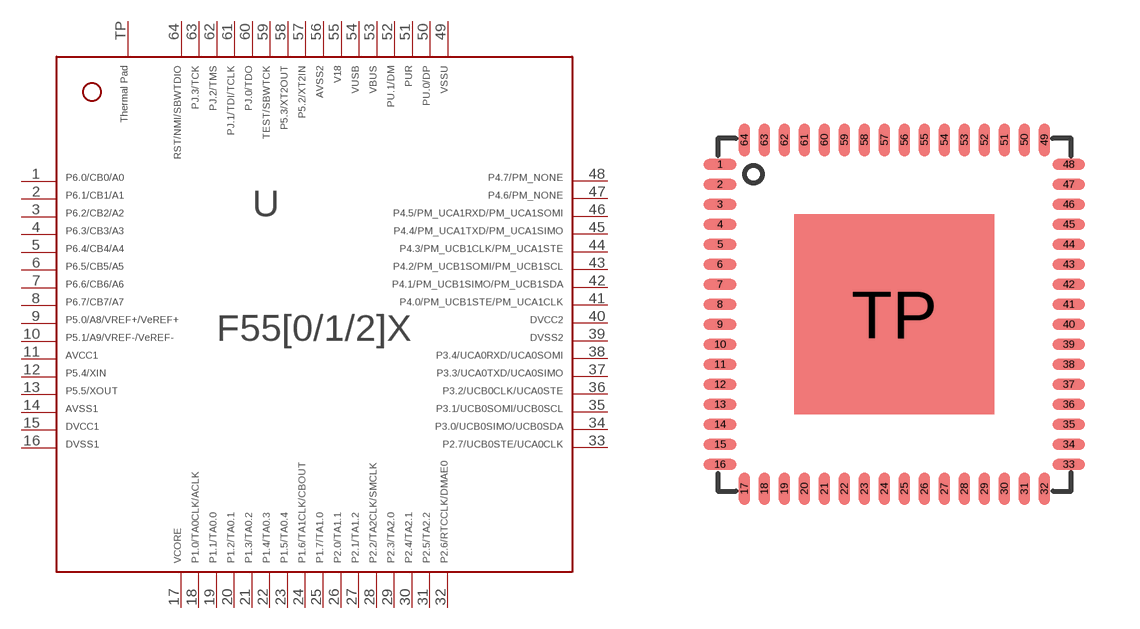
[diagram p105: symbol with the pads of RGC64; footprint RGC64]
Designator prefix -

## F55[0/1/2]X---RGC64  [RGC64]
1  1
2  2
3  3
4  4
5  5
6  6
7  7  nc
8  8  in
9  9  out
10  10
11  11  pwr
12  12
13  13
14  14  pwr
15  15  pwr
16  16  pwr
17  17  pwr
18  18
19  19
20  20
21  21
22  22
23  23
24  24
25  25
26  26
27  27
28  28
29  29
30  30
31  31
32  32
33  33
34  34
35  35
36  36
37  37
38  38
39  39  pwr
40  40  pwr
41  41
42  42
43  43
44  44
45  45
46  46
47  47
48  48
49  49  pwr
50  50
51  51
52  52
53  53  pwr
54  54  pwr
55  55  pwr
56  56  pwr
57  57
58  58
59  59  in
60  60
61  61
62  62
63  63
64  64
TP  TP  pwr

## Footprint RGC64 (pad centres in mm)
*** TI: RGC *** JEDEC: S-PQFP-N64 *** 64 PINS *** ---> PIN 65 (exposed thermal die pad) should be connected with GND
smd 0.825 x 0.28: 1 -4.36,3.75; 2 -4.36,3.25; 3 -4.36,2.75; 4 -4.36,2.25; 5 -4.36,1.75; 6 -4.36,1.25; 7 -4.36,0.75; 8 -4.36,0.25; 9 -4.36,-0.25; 10 -4.36,-0.75; 11 -4.36,-1.25; 12 -4.36,-1.75; 13 -4.36,-2.25; 14 -4.36,-2.75; 15 -4.36,-3.25; 16 -4.36,-3.75; 33 4.36,-3.75; 34 4.36,-3.25; 35 4.36,-2.75; 36 4.36,-2.25; 37 4.36,-1.75; 38 4.36,-1.25; 39 4.36,-0.75; 40 4.36,-0.25; 41 4.36,0.25; 42 4.36,0.75; 43 4.36,1.25; 44 4.36,1.75; 45 4.36,2.25; 46 4.36,2.75; 47 4.36,3.25; 48 4.36,3.75
smd 0.28 x 0.825: 17 -3.75,-4.36; 18 -3.25,-4.36; 19 -2.75,-4.36; 20 -2.25,-4.36; 21 -1.75,-4.36; 22 -1.25,-4.36; 23 -0.75,-4.36; 24 -0.25,-4.36; 25 0.25,-4.36; 26 0.75,-4.36; 27 1.25,-4.36; 28 1.75,-4.36; 29 2.25,-4.36; 30 2.75,-4.36; 31 3.25,-4.36; 32 3.75,-4.36; 49 3.75,4.36; 50 3.25,4.36; 51 2.75,4.36; 52 2.25,4.36; 53 1.75,4.36; 54 1.25,4.36; 55 0.75,4.36; 56 0.25,4.36; 57 -0.25,4.36; 58 -0.75,4.36; 59 -1.25,4.36; 60 -1.75,4.36; 61 -2.25,4.36; 62 -2.75,4.36; 63 -3.25,4.36; 64 -3.75,4.36
smd 5 x 5: TP 0,0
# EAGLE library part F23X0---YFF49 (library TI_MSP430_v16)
***MSP430F23x0***YFF49

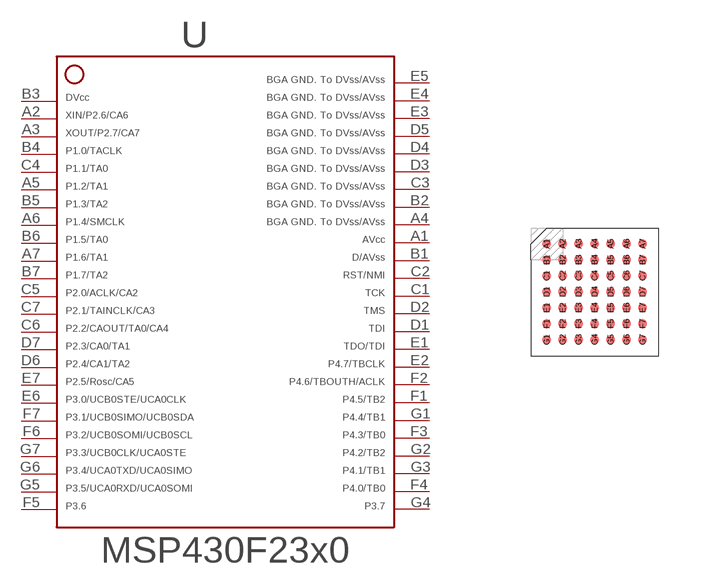
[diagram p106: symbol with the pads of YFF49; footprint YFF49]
Designator prefix -

## F23X0---YFF49  [YFF49]
A1  A1  pwr
A2  A2
A3  A3
A4  A4
A5  A5
A6  A6
A7  A7
B1  B1  pwr
B2  B2
B3  B3  pwr
B4  B4
B5  B5
B6  B6
B7  B7
C1  C1  in
C2  C2  in
C3  C3
C4  C4
C5  C5
C6  C6
C7  C7
D1  D1  in
D2  D2  in
D3  D3
D4  D4
D5  D5
D6  D6
D7  D7
E1  E1
E2  E2
E3  E3
E4  E4
E5  E5
E6  E6
E7  E7
F1  F1
F2  F2
F3  F3
F4  F4
F5  F5
F6  F6
F7  F7
G1  G1
G2  G2
G3  G3
G4  G4
G5  G5
G6  G6
G7  G7

## Footprint YFF49 (pad centres in mm)
*** TI: YFF *** JEDEC: S-XBGA-N49 --- DSBGA *** 49 PINS *** ** 0.4 mm Pitch *** Regarding Soldermask and other limits please check with your PCB Vendor for optimization.
smd 0.23 x 0.23: A1 -1.2,1.2; A2 -0.8,1.2; A3 -0.4,1.2; A4 0,1.2; A5 0.4,1.2; A6 0.8,1.2; A7 1.2,1.2; B1 -1.2,0.8; B2 -0.8,0.8; B3 -0.4,0.8; B4 0,0.8; B5 0.4,0.8; B6 0.8,0.8; B7 1.2,0.8; C1 -1.2,0.4; C2 -0.8,0.4; C3 -0.4,0.4; C4 0,0.4; C5 0.4,0.4; C6 0.8,0.4; C7 1.2,0.4; D1 -1.2,0; D2 -0.8,0; D3 -0.4,0; D4 0,0; D5 0.4,0; D6 0.8,0; D7 1.2,0; E1 -1.2,-0.4; E2 -0.8,-0.4; E3 -0.4,-0.4; E4 0,-0.4; E5 0.4,-0.4; E6 0.8,-0.4; E7 1.2,-0.4; F1 -1.2,-0.8; F2 -0.8,-0.8; F3 -0.4,-0.8; F4 0,-0.8; F5 0.4,-0.8; F6 0.8,-0.8; F7 1.2,-0.8; G1 -1.2,-1.2; G2 -0.8,-1.2; G3 -0.4,-1.2; G4 0,-1.2; G5 0.4,-1.2; G6 0.8,-1.2; G7 1.2,-1.2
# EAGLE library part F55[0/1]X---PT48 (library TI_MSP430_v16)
***F55[0/1/2]X*** PT48 Rev. 1.0 06/2010 "http://www.ti.com/lit/gpn/msp430f5509" Only for FF5504, F5508,F5509,F5510

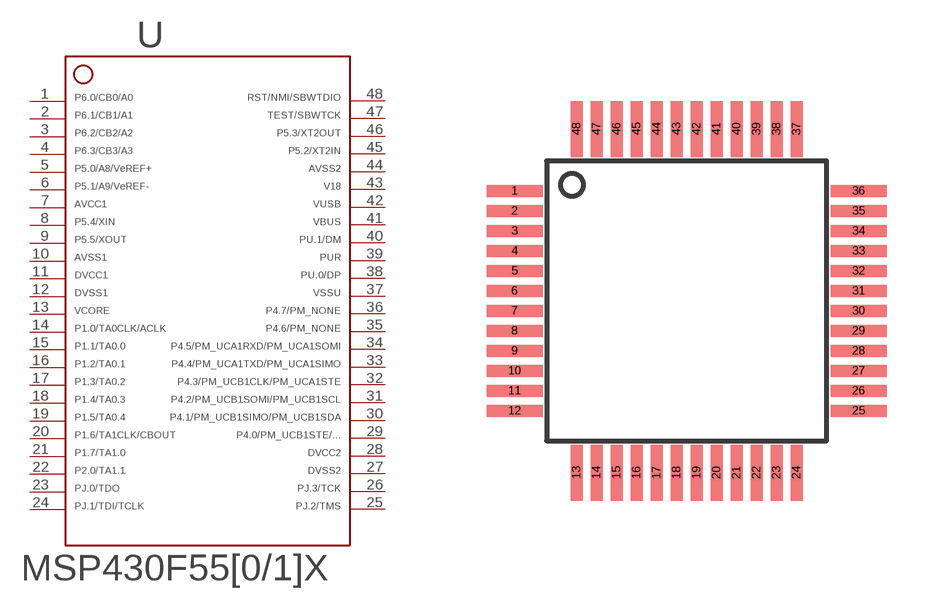
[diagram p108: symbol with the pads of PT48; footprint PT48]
Designator prefix -

## F55[0/1]X---PT48  [PT48]
1  1
2  2
3  3
4  4
5  5
6  6
7  7  pwr
8  8
9  9
10  10  pwr
11  11  pwr
12  12  pwr
13  13  pwr
14  14
15  15
16  16
17  17
18  18
19  19
20  20
21  21
22  22
23  23
24  24
25  25
26  26
27  27  pwr
28  28  pwr
29  29
30  30
31  31
32  32
33  33
34  34
35  35
36  36
37  37  pwr
38  38
39  39
40  40
41  41  pwr
42  42  pwr
43  43  pwr
44  44  pwr
45  45
46  46  pwr
47  47  in
48  48

## Footprint PT48 (pad centres in mm)
*** TI: PT *** JEDEC: S-PQFP-G48 *** 48 PINS ***
smd 1.4 x 0.3: 1 -4.3,2.75; 2 -4.3,2.25; 3 -4.3,1.75; 4 -4.3,1.25; 5 -4.3,0.75; 6 -4.3,0.25; 7 -4.3,-0.25; 8 -4.3,-0.75; 9 -4.3,-1.25; 10 -4.3,-1.75; 11 -4.3,-2.25; 12 -4.3,-2.75; 25 4.3,-2.75; 26 4.3,-2.25; 27 4.3,-1.75; 28 4.3,-1.25; 29 4.3,-0.75; 30 4.3,-0.25; 31 4.3,0.25; 32 4.3,0.75; 33 4.3,1.25; 34 4.3,1.75; 35 4.3,2.25; 36 4.3,2.75
smd 0.3 x 1.4: 13 -2.75,-4.3; 14 -2.25,-4.3; 15 -1.75,-4.3; 16 -1.25,-4.3; 17 -0.75,-4.3; 18 -0.25,-4.3; 19 0.25,-4.3; 20 0.75,-4.3; 21 1.25,-4.3; 22 1.75,-4.3; 23 2.25,-4.3; 24 2.75,-4.3; 37 2.75,4.3; 38 2.25,4.3; 39 1.75,4.3; 40 1.25,4.3; 41 0.75,4.3; 42 0.25,4.3; 43 -0.25,4.3; 44 -0.75,4.3; 45 -1.25,4.3; 46 -1.75,4.3; 47 -2.25,4.3; 48 -2.75,4.3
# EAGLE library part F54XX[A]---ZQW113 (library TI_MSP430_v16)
***MSP430F54xx[A]***ZQW113

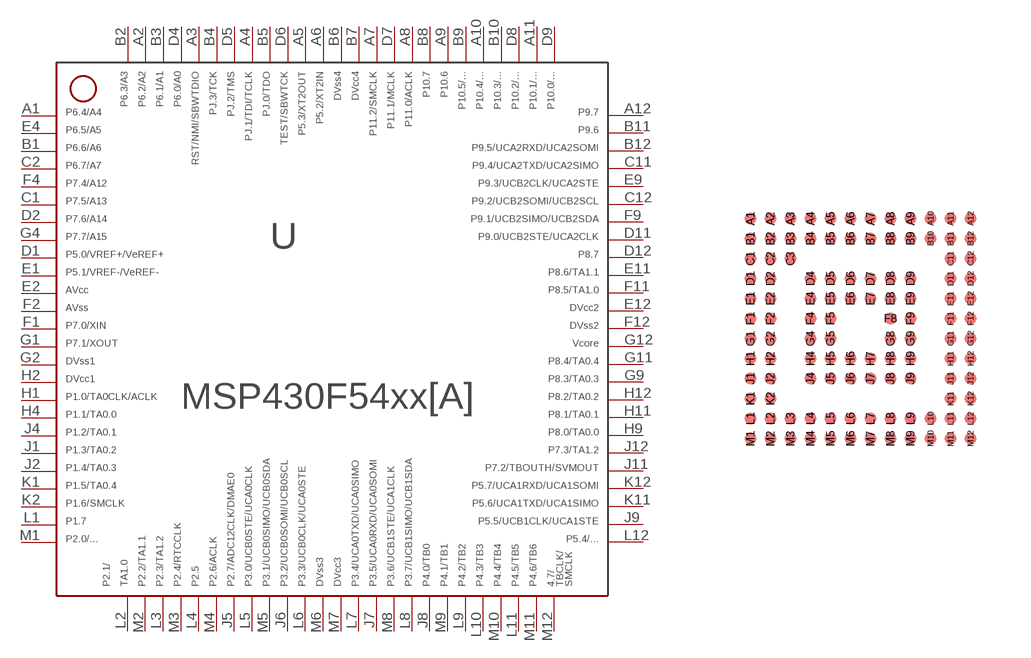
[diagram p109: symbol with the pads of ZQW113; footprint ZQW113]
Designator prefix -

## F54XX[A]---ZQW113  [ZQW113]
A1  A1
A2  A2
A3  A3
A4  A4
A5  A5
A6  A6
A7  A7
A8  A8
A9  A9
A10  A10
A11  A11
A12  A12
B1  B1
B2  B2
B3  B3
B4  B4
B5  B5
B6  B6  pwr
B7  B7  pwr
B8  B8
B9  B9
B10  B10
B11  B11
B12  B12
C1  C1
C2  C2
C11  C11
C12  C12
D1  D1
D2  D2
D4  D4
D5  D5
D6  D6  in
D7  D7
D8  D8
D9  D9
D11  D11
D12  D12
E1  E1
E2  E2  pwr
E4  E4
E9  E9
E11  E11
E12  E12  pwr
F1  F1
F2  F2  pwr
F4  F4
F9  F9
F11  F11
F12  F12  pwr
G1  G1
G2  G2  pwr
G4  G4
G9  G9
G11  G11
G12  G12  pwr
H1  H1
H2  H2  pwr
H4  H4
H9  H9
H11  H11
H12  H12
J1  J1
J2  J2
J4  J4
J5  J5
J6  J6
J7  J7
J8  J8
J9  J9
J11  J11
J12  J12
K1  K1
K2  K2
K11  K11
K12  K12
L1  L1
L2  L2
L3  L3
L4  L4
L5  L5
L6  L6
L7  L7
L8  L8
L9  L9
L10  L10
L11  L11
L12  L12
M1  M1
M2  M2
M3  M3
M4  M4
M5  M5
M6  M6  pwr
M7  M7  pwr
M8  M8
M9  M9
M10  M10
M11  M11
M12  M12

## Footprint ZQW113 (pad centres in mm)
ZQW113 BGA package; 0.5mm pitch
smd 0.3 x 0.3: A1 0.75,6.25; A2 1.25,6.25; A3 1.75,6.25; A4 2.25,6.25; A5 2.75,6.25; A6 3.25,6.25; A7 3.75,6.25; A8 4.25,6.25; A9 4.75,6.25; A10 5.25,6.25; A11 5.75,6.25; A12 6.25,6.25; B1 0.75,5.75; B2 1.25,5.75; B3 1.75,5.75; B4 2.25,5.75; B5 2.75,5.75; B6 3.25,5.75; B7 3.75,5.75; B8 4.25,5.75; B9 4.75,5.75; B10 5.25,5.75; B11 5.75,5.75; B12 6.25,5.75; C1 0.75,5.25; C2 1.25,5.25; C3 1.75,5.25; C11 5.75,5.25; C12 6.25,5.25; D1 0.75,4.75; D2 1.25,4.75; D4 2.25,4.75; D5 2.75,4.75; D6 3.25,4.75; D7 3.75,4.75; D8 4.25,4.75; D9 4.75,4.75; D11 5.75,4.75; D12 6.25,4.75; E1 0.75,4.25; E2 1.25,4.25; E4 2.25,4.25; E5 2.75,4.25; E6 3.25,4.25; E7 3.75,4.25; E8 4.25,4.25; E9 4.75,4.25; E11 5.75,4.25; E12 6.25,4.25; F1 0.75,3.75; F2 1.25,3.75; F4 2.25,3.75; F5 2.75,3.75; F8 4.25,3.75; F9 4.75,3.75; F11 5.75,3.75; F12 6.25,3.75; G1 0.75,3.25; G2 1.25,3.25; G4 2.25,3.25; G5 2.75,3.25; G8 4.25,3.25; G9 4.75,3.25; G11 5.75,3.25; G12 6.25,3.25; H1 0.75,2.75; H2 1.25,2.75; H4 2.25,2.75; H5 2.75,2.75; H6 3.25,2.75; H7 3.75,2.75; H8 4.25,2.75; H9 4.75,2.75; H11 5.75,2.75; H12 6.25,2.75; J1 0.75,2.25; J2 1.25,2.25; J4 2.25,2.25; J5 2.75,2.25; J6 3.25,2.25; J7 3.75,2.25; J8 4.25,2.25; J9 4.75,2.25; J11 5.75,2.25; J12 6.25,2.25; K1 0.75,1.75; K2 1.25,1.75; K11 5.75,1.75; K12 6.25,1.75; L1 0.75,1.25; L2 1.25,1.25; L3 1.75,1.25; L4 2.25,1.25; L5 2.75,1.25; L6 3.25,1.25; L7 3.75,1.25; L8 4.25,1.25; L9 4.75,1.25; L10 5.25,1.25; L11 5.75,1.25; L12 6.25,1.25; M1 0.75,0.75; M2 1.25,0.75; M3 1.75,0.75; M4 2.25,0.75; M5 2.75,0.75; M6 3.25,0.75; M7 3.75,0.75; M8 4.25,0.75; M9 4.75,0.75; M10 5.25,0.75; M11 5.75,0.75; M12 6.25,0.75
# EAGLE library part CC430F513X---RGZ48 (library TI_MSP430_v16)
***CC430F513X***RGZ48 ** ** Rev 1.0 ** 06/2010 * http://focus.ti.com/docs/prod/folders/print/cc430f5137.html

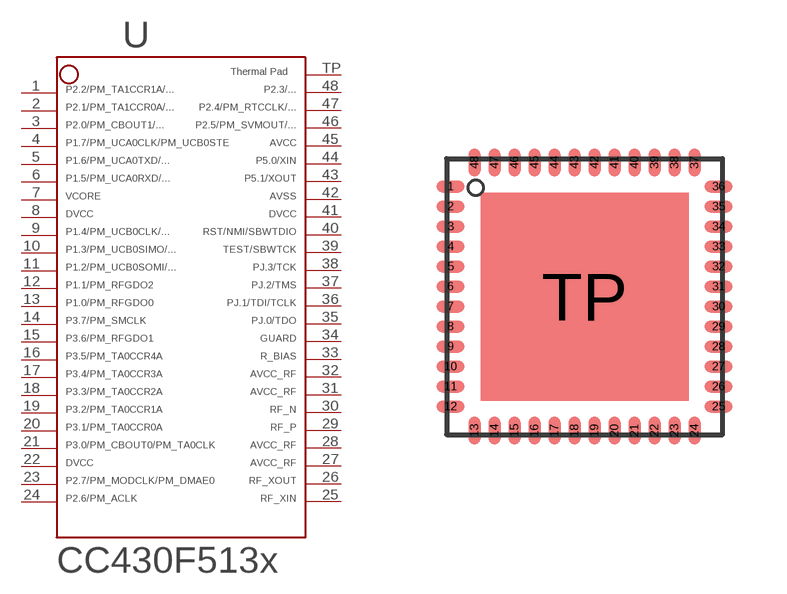
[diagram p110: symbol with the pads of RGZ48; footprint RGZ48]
Designator prefix -

## CC430F513X---RGZ48  [RGZ48]
1  1
2  2
3  3
4  4
5  5
6  6
7  7  pwr
8  8  pwr
9  9
10  10
11  11
12  12
13  13
14  14
15  15
16  16
17  17
18  18
19  19
20  20
21  21
22  22  pwr
23  23
24  24
25  25  in
26  26  out
27  27  pwr
28  28
29  29
30  30
31  31  pwr
32  32  pwr
33  33  pwr
34  34  pwr
35  35
36  36
37  37
38  38
39  39  in
40  40
41  41  pwr
42  42  pwr
43  43  in
44  44  in
45  45  in
46  46
47  47  in
48  48
TP  49  pwr

## Footprint RGZ48 (pad centres in mm)
*** TI: RGZ *** JEDEC: S-PQFP-N48 *** 48 PINS *** ---> PIN TP (exposed thermal die pad) should be connected with GND
smd 0.7 x 0.3: 1 -3.35,2.75; 2 -3.35,2.25; 3 -3.35,1.75; 4 -3.35,1.25; 5 -3.35,0.75; 6 -3.35,0.25; 7 -3.35,-0.25; 8 -3.35,-0.75; 9 -3.35,-1.25; 10 -3.35,-1.75; 11 -3.35,-2.25; 12 -3.35,-2.75; 25 3.35,-2.75; 26 3.35,-2.25; 27 3.35,-1.75; 28 3.35,-1.25; 29 3.35,-0.75; 30 3.35,-0.25; 31 3.35,0.25; 32 3.35,0.75; 33 3.35,1.25; 34 3.35,1.75; 35 3.35,2.25; 36 3.35,2.75
smd 0.3 x 0.7: 13 -2.75,-3.35; 14 -2.25,-3.35; 15 -1.75,-3.35; 16 -1.25,-3.35; 17 -0.75,-3.35; 18 -0.25,-3.35; 19 0.25,-3.35; 20 0.75,-3.35; 21 1.25,-3.35; 22 1.75,-3.35; 23 2.25,-3.35; 24 2.75,-3.35; 37 2.75,3.35; 38 2.25,3.35; 39 1.75,3.35; 40 1.25,3.35; 41 0.75,3.35; 42 0.25,3.35; 43 -0.25,3.35; 44 -0.75,3.35; 45 -1.25,3.35; 46 -1.75,3.35; 47 -2.25,3.35; 48 -2.75,3.35
smd 5.2 x 5.2: TP 0,0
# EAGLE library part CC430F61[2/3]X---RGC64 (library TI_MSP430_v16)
***CC430F61[2/3]X***RGC64 ** ** Rev 1.0 ** 06/2010 * http://focus.ti.com/docs/prod/folders/print/cc430f6137.html

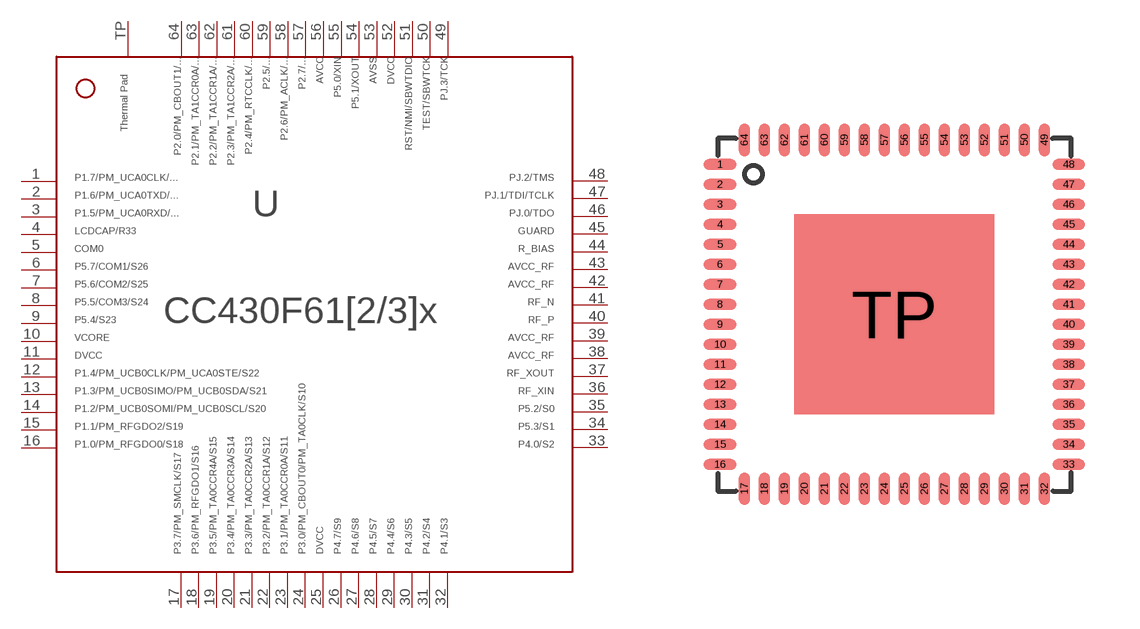
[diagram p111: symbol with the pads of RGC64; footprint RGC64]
Designator prefix -

## CC430F61[2/3]X---RGC64  [RGC64]
1  1
2  2
3  3
4  4
5  5  out
6  6
7  7
8  8  in
9  9
10  10  pwr
11  11  pwr
12  12
13  13
14  14
15  15
16  16
17  17
18  18
19  19
20  20
21  21
22  22
23  23
24  24
25  25  pwr
26  26
27  27
28  28
29  29
30  30
31  31
32  32
33  33
34  34
35  35
36  36  in
37  37  out
38  38  pwr
39  39  pwr
40  40
41  41
42  42  pwr
43  43  pwr
44  44  pwr
45  45  pwr
46  46
47  47
48  48
49  49
50  50  in
51  51
52  52  pwr
53  53  pwr
54  54
55  55  in
56  56  pwr
57  57  in
58  58  in
59  59
60  60
61  61
62  62
63  63
64  64
TP  TP  pwr

## Footprint RGC64 (pad centres in mm)
*** TI: RGC *** JEDEC: S-PQFP-N64 *** 64 PINS *** ---> PIN 65 (exposed thermal die pad) should be connected with GND
smd 0.825 x 0.28: 1 -4.36,3.75; 2 -4.36,3.25; 3 -4.36,2.75; 4 -4.36,2.25; 5 -4.36,1.75; 6 -4.36,1.25; 7 -4.36,0.75; 8 -4.36,0.25; 9 -4.36,-0.25; 10 -4.36,-0.75; 11 -4.36,-1.25; 12 -4.36,-1.75; 13 -4.36,-2.25; 14 -4.36,-2.75; 15 -4.36,-3.25; 16 -4.36,-3.75; 33 4.36,-3.75; 34 4.36,-3.25; 35 4.36,-2.75; 36 4.36,-2.25; 37 4.36,-1.75; 38 4.36,-1.25; 39 4.36,-0.75; 40 4.36,-0.25; 41 4.36,0.25; 42 4.36,0.75; 43 4.36,1.25; 44 4.36,1.75; 45 4.36,2.25; 46 4.36,2.75; 47 4.36,3.25; 48 4.36,3.75
smd 0.28 x 0.825: 17 -3.75,-4.36; 18 -3.25,-4.36; 19 -2.75,-4.36; 20 -2.25,-4.36; 21 -1.75,-4.36; 22 -1.25,-4.36; 23 -0.75,-4.36; 24 -0.25,-4.36; 25 0.25,-4.36; 26 0.75,-4.36; 27 1.25,-4.36; 28 1.75,-4.36; 29 2.25,-4.36; 30 2.75,-4.36; 31 3.25,-4.36; 32 3.75,-4.36; 49 3.75,4.36; 50 3.25,4.36; 51 2.75,4.36; 52 2.25,4.36; 53 1.75,4.36; 54 1.25,4.36; 55 0.75,4.36; 56 0.25,4.36; 57 -0.25,4.36; 58 -0.75,4.36; 59 -1.25,4.36; 60 -1.75,4.36; 61 -2.25,4.36; 62 -2.75,4.36; 63 -3.25,4.36; 64 -3.75,4.36
smd 5 x 5: TP 0,0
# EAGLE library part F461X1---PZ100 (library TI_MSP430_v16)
***MSP430F461X*** PZ100 http://focus.ti.com/docs/prod/folders/print/msp430f46191.html Rev1.0 06/2010

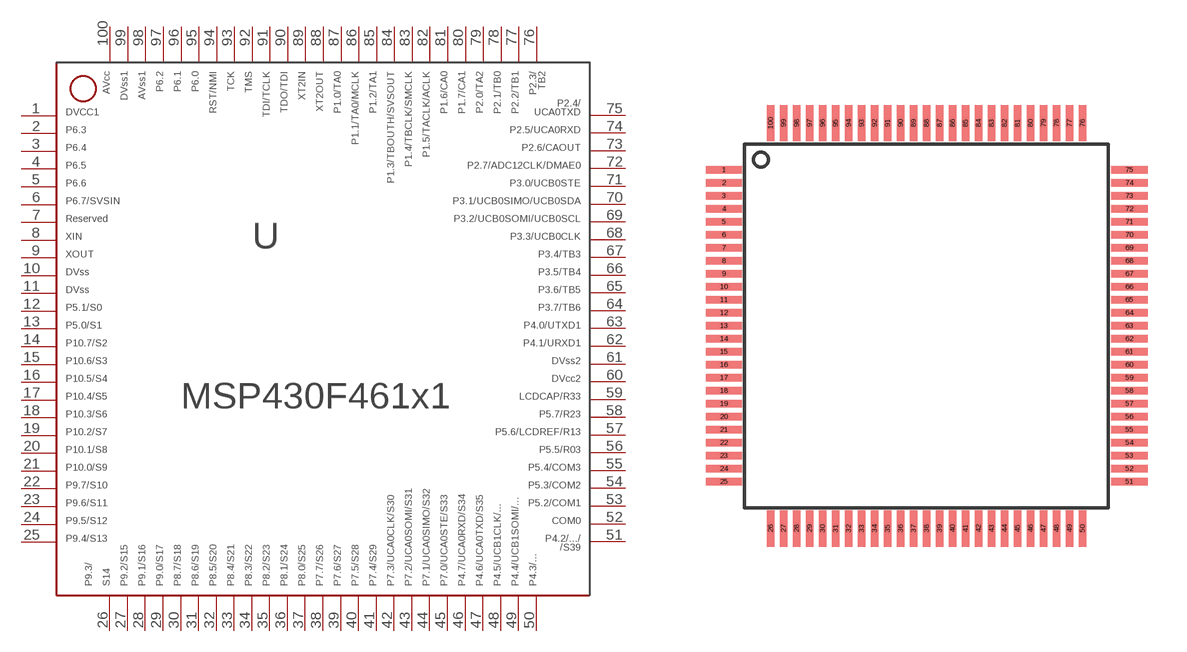
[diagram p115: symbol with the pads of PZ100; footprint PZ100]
Designator prefix -

## F461X1---PZ100  [PZ100]
1  1  pwr
2  2  in
3  3  in
4  4  in
5  5  in
6  6  in
7  7  in
8  8  in
9  9  out
10  10
11  11  nc
12  12
13  13  out
14  14
15  15
16  16
17  17
18  18
19  19
20  20
21  21
22  22
23  23
24  24
25  25
26  26
27  27
28  28
29  29
30  30
31  31
32  32
33  33
34  34
35  35
36  36
37  37
38  38
39  39
40  40
41  41
42  42
43  43
44  44
45  45
46  46
47  47
48  48
49  49
50  50
51  51
52  52  out
53  53
54  54
55  55
56  56  in
57  57
58  58
59  59
60  60  pwr
61  61  pwr
62  62
63  63
64  64
65  65
66  66
67  67
68  68  out
69  69
70  70
71  71
72  72
73  73
74  74
75  75
76  76
77  77
78  78
79  79
80  80
81  81
82  82
83  83
84  84
85  85
86  86
87  87
88  88  out
89  89  in
90  90
91  91  in
92  92  in
93  93  in
94  94  in
95  95
96  96
97  97
98  98  pwr
99  99  pwr
100  100  pwr

## Footprint PZ100 (pad centres in mm)
*** TI: PZ *** JEDEC: S-PQFP-G100 *** 100 PINS ***
smd 1.4 x 0.3: 1 -7.8,6; 2 -7.8,5.5; 3 -7.8,5; 4 -7.8,4.5; 5 -7.8,4; 6 -7.8,3.5; 7 -7.8,3; 8 -7.8,2.5; 9 -7.8,2; 10 -7.8,1.5; 11 -7.8,1; 12 -7.8,0.5; 13 -7.8,0; 14 -7.8,-0.5; 15 -7.8,-1; 16 -7.8,-1.5; 17 -7.8,-2; 18 -7.8,-2.5; 19 -7.8,-3; 20 -7.8,-3.5; 21 -7.8,-4; 22 -7.8,-4.5; 23 -7.8,-5; 24 -7.8,-5.5; 25 -7.8,-6; 51 7.8,-6; 52 7.8,-5.5; 53 7.8,-5; 54 7.8,-4.5; 55 7.8,-4; 56 7.8,-3.5; 57 7.8,-3; 58 7.8,-2.5; 59 7.8,-2; 60 7.8,-1.5; 61 7.8,-1; 62 7.8,-0.5; 63 7.8,0; 64 7.8,0.5; 65 7.8,1; 66 7.8,1.5; 67 7.8,2; 68 7.8,2.5; 69 7.8,3; 70 7.8,3.5; 71 7.8,4; 72 7.8,4.5; 73 7.8,5; 74 7.8,5.5; 75 7.8,6
smd 0.3 x 1.4: 26 -6,-7.8; 27 -5.5,-7.8; 28 -5,-7.8; 29 -4.5,-7.8; 30 -4,-7.8; 31 -3.5,-7.8; 32 -3,-7.8; 33 -2.5,-7.8; 34 -2,-7.8; 35 -1.5,-7.8; 36 -1,-7.8; 37 -0.5,-7.8; 38 0,-7.8; 39 0.5,-7.8; 40 1,-7.8; 41 1.5,-7.8; 42 2,-7.8; 43 2.5,-7.8; 44 3,-7.8; 45 3.5,-7.8; 46 4,-7.8; 47 4.5,-7.8; 48 5,-7.8; 49 5.5,-7.8; 50 6,-7.8; 76 6,7.8; 77 5.5,7.8; 78 5,7.8; 79 4.5,7.8; 80 4,7.8; 81 3.5,7.8; 82 3,7.8; 83 2.5,7.8; 84 2,7.8; 85 1.5,7.8; 86 1,7.8; 87 0.5,7.8; 88 0,7.8; 89 -0.5,7.8; 90 -1,7.8; 91 -1.5,7.8; 92 -2,7.8; 93 -2.5,7.8; 94 -3,7.8; 95 -3.5,7.8; 96 -4,7.8; 97 -4.5,7.8; 98 -5,7.8; 99 -5.5,7.8; 100 -6,7.8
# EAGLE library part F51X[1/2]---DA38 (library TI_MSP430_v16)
***MSP430F51x2***DA38 Rev 1.0 *** 06/2010

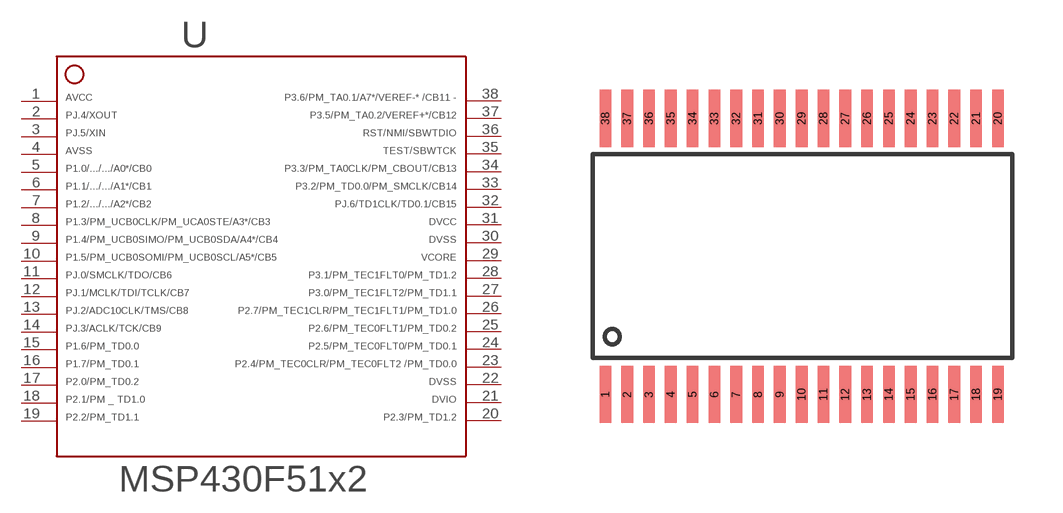
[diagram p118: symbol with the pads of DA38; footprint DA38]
Designator prefix -

## F51X[1/2]---DA38  [DA38]
1  1  pwr
2  2
3  3
4  4  pwr
5  5
6  6
7  7
8  8
9  9
10  10
11  11
12  12
13  13  pwr
14  14  pwr
15  15
16  16
17  17
18  18
19  19
20  20
21  21
22  22
23  23
24  24
25  25
26  26
27  27
28  28
29  29
30  30
31  31
32  32
33  33
34  34
35  35
36  36
37  37  in
38  38  pwr

## Footprint DA38 (pad centres in mm)
*** TI: DA *** JEDEC: R-PDSO-G28 *** 38 PINS ***
smd 0.35 x 1.705: 1 -5.85,-4.12; 2 -5.2,-4.12; 3 -4.55,-4.12; 4 -3.9,-4.12; 5 -3.25,-4.12; 6 -2.6,-4.12; 7 -1.95,-4.12; 8 -1.3,-4.12; 9 -0.65,-4.12; 10 0,-4.12; 11 0.65,-4.12; 12 1.3,-4.12; 13 1.95,-4.12; 14 2.6,-4.12; 15 3.25,-4.12; 16 3.9,-4.12; 17 4.55,-4.12; 18 5.2,-4.12; 19 5.85,-4.12; 20 5.85,4.12; 21 5.2,4.12; 22 4.55,4.12; 23 3.9,4.12; 24 3.25,4.12; 25 2.6,4.12; 26 1.95,4.12; 27 1.3,4.12; 28 0.65,4.12; 29 0,4.12; 30 -0.65,4.12; 31 -1.3,4.12; 32 -1.95,4.12; 33 -2.6,4.12; 34 -3.25,4.12; 35 -3.9,4.12; 36 -4.55,4.12; 37 -5.2,4.12; 38 -5.85,4.12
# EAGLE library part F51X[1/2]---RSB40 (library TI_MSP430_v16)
***MSP430F51x2***RSB40 Rev 1.0 *** 06/2010

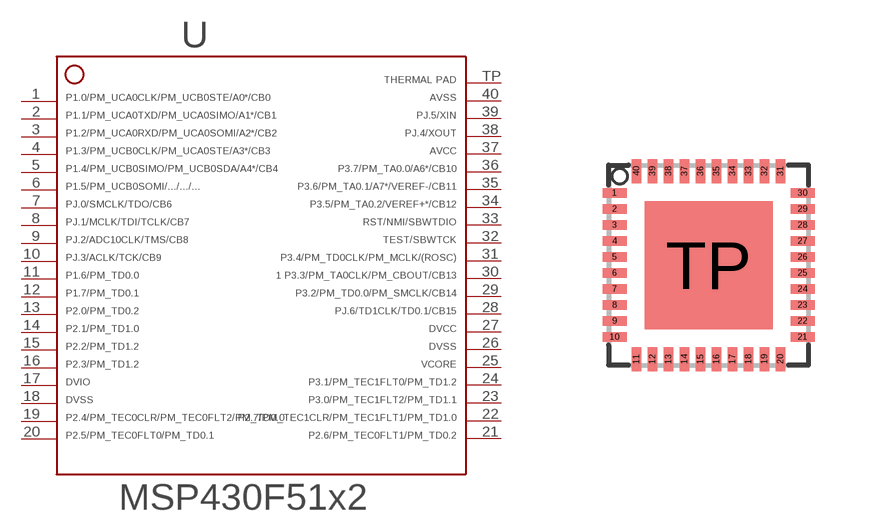
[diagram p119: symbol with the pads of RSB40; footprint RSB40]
Designator prefix -

## F51X[1/2]---RSB40  [RSB40]
1  1  pwr
2  2
3  3
4  4  pwr
5  5
6  6
7  7
8  8
9  9
10  10
11  11
12  12
13  13  pwr
14  14  pwr
15  15
16  16
17  17
18  18
19  19
20  20
21  21
22  22
23  23
24  24
25  25
26  26
27  27
28  28
29  29
30  30
31  31
32  32
33  33
34  34
35  35
36  36
37  37  in
38  38  pwr
39  39  pwr
40  40
TP  TP  pwr

## Footprint RSB40 (pad centres in mm)
*** TI: RSB *** JEDEC: S-PQFP-N40 *** 40 PINS *** ---> PIN TP (exposed thermal die pad) should be connected with GND *** Regarding Soldermask and other limits please check with your PCB Vendor for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
smd 0.6 x 0.23: 1 -2.35,1.8; 2 -2.35,1.4; 3 -2.35,1; 4 -2.35,0.6; 5 -2.35,0.2; 6 -2.35,-0.2; 7 -2.35,-0.6; 8 -2.35,-1; 9 -2.35,-1.4; 10 -2.35,-1.8; 21 2.35,-1.8; 22 2.35,-1.4; 23 2.35,-1; 24 2.35,-0.6; 25 2.35,-0.2; 26 2.35,0.2; 27 2.35,0.6; 28 2.35,1; 29 2.35,1.4; 30 2.35,1.8
smd 0.23 x 0.6: 11 -1.8,-2.35; 12 -1.4,-2.35; 13 -1,-2.35; 14 -0.6,-2.35; 15 -0.2,-2.35; 16 0.2,-2.35; 17 0.6,-2.35; 18 1,-2.35; 19 1.4,-2.35; 20 1.8,-2.35; 31 1.8,2.35; 32 1.4,2.35; 33 1,2.35; 34 0.6,2.35; 35 0.2,2.35; 36 -0.2,2.35; 37 -0.6,2.35; 38 -1,2.35; 39 -1.4,2.35; 40 -1.8,2.35
smd 3.2 x 3.2: TP 0,0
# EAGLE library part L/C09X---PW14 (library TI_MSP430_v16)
MSP430[L/C]09X *** PW14 ** Rev 1.0 *** 06/2010

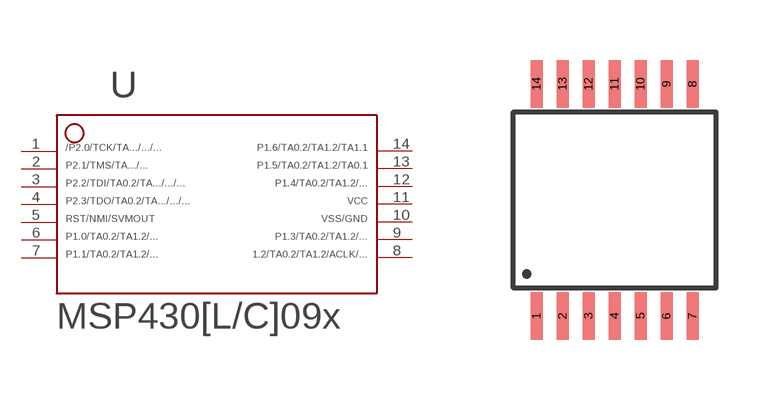
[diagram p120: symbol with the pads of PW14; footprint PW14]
Designator prefix -

## L/C09X---PW14  [PW14]
1  1  pwr
2  2
3  3
4  4
5  5
6  6
7  7
8  8
9  9
10  10
11  11  in
12  12
13  13
14  14  pwr

## Footprint PW14 (pad centres in mm)
*** TI: PW *** JEDEC: R-PDSO-G14 *** 14 PINS ***
smd 0.3 x 1.2: 1 -1.95,-2.9; 2 -1.3,-2.9; 3 -0.65,-2.9; 4 0,-2.9; 5 0.65,-2.9; 6 1.3,-2.9; 7 1.95,-2.9; 8 1.95,2.9; 9 1.3,2.9; 10 0.65,2.9; 11 0,2.9; 12 -0.65,2.9; 13 -1.3,2.9; 14 -1.95,2.9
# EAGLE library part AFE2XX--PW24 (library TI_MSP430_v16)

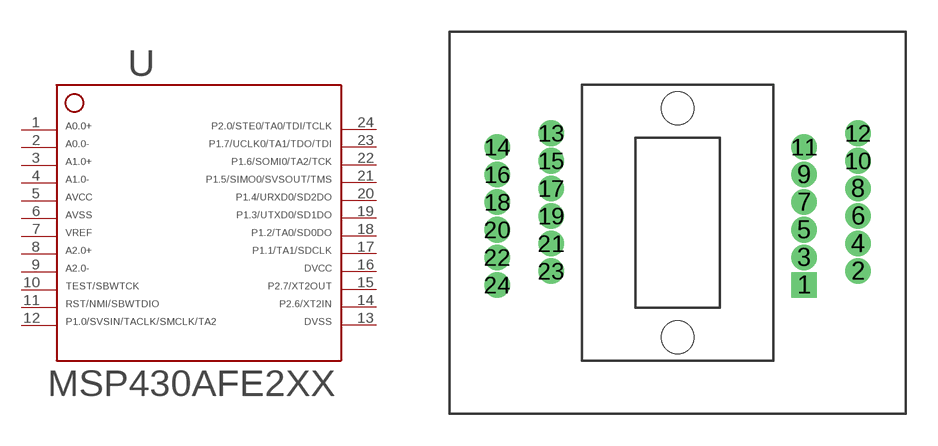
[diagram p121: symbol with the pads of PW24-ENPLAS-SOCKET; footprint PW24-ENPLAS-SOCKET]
Designator prefix -

## AFE2XX--PW24  [PW24-ENPLAS-SOCKET]
1  1  in
2  2  pwr
3  3
4  4  pwr
5  5  out
6  6  in
7  7  in
8  8
9  9
10  10
11  11
12  12
13  13
14  14
15  15
16  16
17  17
18  18
19  19
20  20
21  21
22  22
23  23
24  24

## Footprint PW24-ENPLAS-SOCKET (pad centres in mm)
OTS-24(28)-0.65-02-00
drill 0.7 pad 1.1 square: 1 5.96,-2.925
drill 0.7 pad 1.1 round: 2 8.5,-2.275; 3 5.96,-1.625; 4 8.5,-0.975; 5 5.96,-0.325; 6 8.5,0.325; 7 5.96,0.975; 8 8.5,1.625; 9 5.96,2.275; 10 8.5,2.925; 11 5.96,3.575; 12 8.5,4.225; 13 -5.96,4.225; 14 -8.5,3.575; 15 -5.96,2.925; 16 -8.5,2.275; 17 -5.96,1.625; 18 -8.5,0.975; 19 -5.96,0.325; 20 -8.5,-0.325; 21 -5.96,-0.975; 22 -8.5,-1.625; 23 -5.96,-2.275; 24 -8.5,-2.925
hole 1.55 at 0,-5.4
hole 1.55 at 0,5.4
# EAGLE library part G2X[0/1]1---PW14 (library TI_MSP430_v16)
MSP430G2X[0/1]1 MSP430G2001, MSP430G2101, MSP430G2201,MSP430G2111, G2211 TSSOP (PW) 14 Pin Package http://focus.ti.com/docs/prod/folders/print/msp430g2111.html

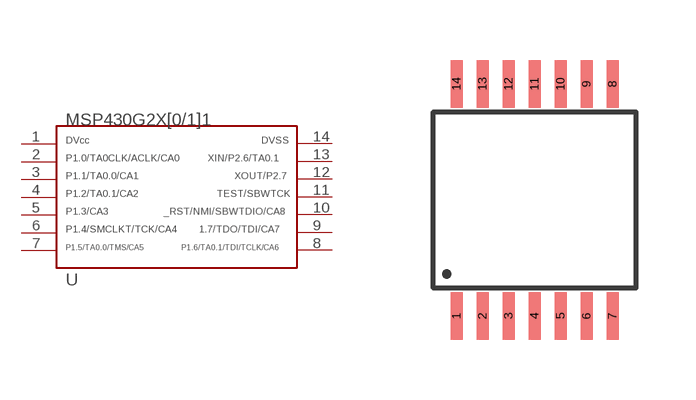
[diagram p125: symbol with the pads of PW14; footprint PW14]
Designator prefix -

## G2X[0/1]1---PW14  [PW14]
1  1
2  2
3  3
4  4
5  5
6  6
7  7
8  8
9  9
10  10
11  11
12  12
13  13
14  14

## Footprint PW14 (pad centres in mm)
*** TI: PW *** JEDEC: R-PDSO-G14 *** 14 PINS ***
smd 0.3 x 1.2: 1 -1.95,-2.9; 2 -1.3,-2.9; 3 -0.65,-2.9; 4 0,-2.9; 5 0.65,-2.9; 6 1.3,-2.9; 7 1.95,-2.9; 8 1.95,2.9; 9 1.3,2.9; 10 0.65,2.9; 11 0,2.9; 12 -0.65,2.9; 13 -1.3,2.9; 14 -1.95,2.9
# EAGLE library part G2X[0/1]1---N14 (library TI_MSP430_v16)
MSP430G2X[0/1]1 MSP430G2001, MSP430G2101, MSP430G2201,MSP430G2111, G2211 PDIP (N) 14 Pin Package http://focus.ti.com/docs/prod/folders/print/msp430g2111.html

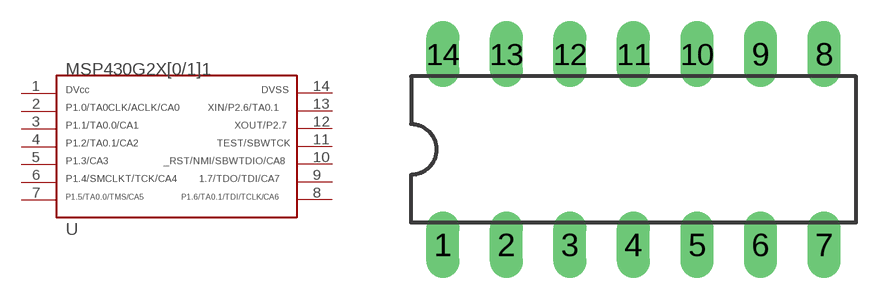
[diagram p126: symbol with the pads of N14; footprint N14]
Designator prefix -

## G2X[0/1]1---N14  [N14]
1  1
2  2
3  3
4  4
5  5
6  6
7  7
8  8
9  9
10  10
11  11
12  12
13  13
14  14

## Footprint N14 (pad centres in mm)
*** TI: N *** JEDEC: R-PDIP-T14 *** 14 PINS *** ** Plastic In-Line
drill 0.813 long: 1 -7.625,-3.81; 2 -5.085,-3.81; 3 -2.545,-3.81; 4 -0.005,-3.81; 5 2.535,-3.81; 6 5.075,-3.81; 7 7.615,-3.81; 8 7.615,3.81; 9 5.075,3.81; 10 2.535,3.81; 11 -0.005,3.81; 12 -2.545,3.81; 13 -5.085,3.81; 14 -7.625,3.81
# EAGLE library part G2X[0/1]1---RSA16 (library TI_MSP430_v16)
MSP430G2X[0/1]1 MSP430G2x11, MSP430G2x01 QFN (RSA) 16 Pin Package http://focus.ti.com/docs/prod/folders/print/msp430g2111.html

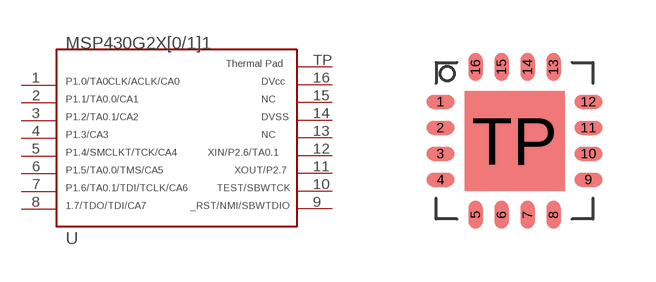
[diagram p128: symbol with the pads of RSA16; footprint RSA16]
Designator prefix -

## G2X[0/1]1---RSA16  [RSA16]
1  1
2  2
3  3
4  4
5  5
6  6
7  7
8  8
9  9
10  10
11  11
12  12
13  13
14  14
15  15
16  16
TP  TP

## Footprint RSA16 (pad centres in mm)
*** TI: RSA *** JEDEC: S-PQFP-N16 *** 16 PINS *** ---> PIN TP (exposed thermal die pad) should be connected with GND
smd 0.7 x 0.35: 1 -1.85,0.975; 2 -1.85,0.325; 3 -1.85,-0.325; 4 -1.85,-0.975; 9 1.85,-0.975; 10 1.85,-0.325; 11 1.85,0.325; 12 1.85,0.975
smd 0.35 x 0.7: 5 -0.975,-1.85; 6 -0.325,-1.85; 7 0.325,-1.85; 8 0.975,-1.85; 13 0.975,1.85; 14 0.325,1.85; 15 -0.325,1.85; 16 -0.975,1.85
smd 2.5 x 2.5: TP 0,0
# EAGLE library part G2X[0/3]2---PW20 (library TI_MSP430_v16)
MSP430G2X[0/3]2 MSP430G2x32, MSP430G2x02 TSSOP (PW) 20 Pin Package http://focus.ti.com/docs/prod/folders/print/msp430g2432.html

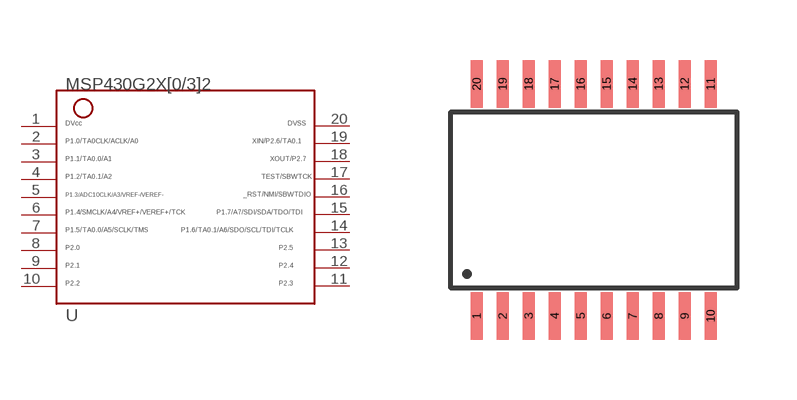
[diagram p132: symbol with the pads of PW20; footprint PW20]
Designator prefix -

## G2X[0/3]2---PW20  [PW20]
1  1
2  2
3  3
4  4
5  5
6  6
7  7
8  8
9  9
10  10
11  11
12  12
13  13
14  14
15  15
16  16
17  17
18  18
19  19
20  20

## Footprint PW20 (pad centres in mm)
*** TI: PW *** JEDEC: R-PDSO-G20 *** 20 PINS ***
smd 0.3 x 1.2: 1 -2.925,-2.9; 2 -2.275,-2.9; 3 -1.625,-2.9; 4 -0.975,-2.9; 5 -0.325,-2.9; 6 0.325,-2.9; 7 0.975,-2.9; 8 1.625,-2.9; 9 2.275,-2.9; 10 2.925,-2.9; 11 2.925,2.9; 12 2.275,2.9; 13 1.625,2.9; 14 0.975,2.9; 15 0.325,2.9; 16 -0.325,2.9; 17 -0.975,2.9; 18 -1.625,2.9; 19 -2.275,2.9; 20 -2.925,2.9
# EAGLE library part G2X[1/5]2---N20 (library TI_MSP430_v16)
MSP430G2X[1/5]2 MSP430G2x52, MSP430G2x12 PDIP (N) 20 Pin Package http://focus.ti.com/docs/prod/folders/print/msp430g2452.html

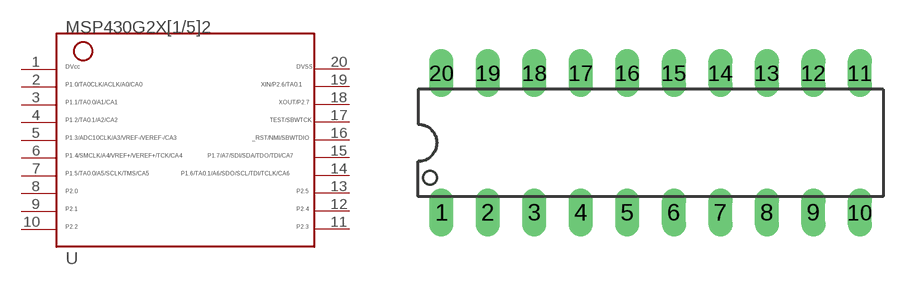
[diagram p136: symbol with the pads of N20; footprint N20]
Designator prefix -

## G2X[1/5]2---N20  [N20]
1  1
2  2
3  3
4  4
5  5
6  6
7  7
8  8
9  9
10  10
11  11
12  12
13  13
14  14
15  15
16  16
17  17
18  18
19  19
20  20

## Footprint N20 (pad centres in mm)
drill 0.813 long: 1 -11.435,-3.81; 2 -8.895,-3.81; 3 -6.355,-3.81; 4 -3.815,-3.81; 5 -1.275,-3.81; 6 1.265,-3.81; 7 3.805,-3.81; 8 6.345,-3.81; 9 8.885,-3.81; 10 11.425,-3.81; 11 11.425,3.81; 12 8.885,3.81; 13 6.345,3.81; 14 3.805,3.81; 15 1.265,3.81; 16 -1.275,3.81; 17 -3.815,3.81; 18 -6.355,3.81; 19 -8.895,3.81; 20 -11.435,3.81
